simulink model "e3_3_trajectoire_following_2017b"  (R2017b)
settings: Solver=FixedStepAuto  StartTime=0.0  StopTime=100  FixedStep=1/120  RelTol=1e-3  EnableMultiTasking=on
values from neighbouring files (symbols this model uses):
  a = XMAX    (= 0.8)    [start_tello.m]
  b = YMAX    (= 1.2)    [start_tello.m]
  battery_threshold = 15    [start_tello.m]
  bb = (ZMIN*YMAX - ZMAX*YMIN)/(YMAX - YMIN)    (= -1.05)    [start_tello.m]
  k = (ZMAX - ZMIN)/(YMAX - YMIN)    (= 0.458333333333)    [start_tello.m]
  omega = 0.3    [start_tello.m]
  R = 1    [start_tello.m]
  sim_end_time = 15*act_end + 4    (= 475.238898038)    [start_tello.m]
  tb2 = tb    (= 2.7)    [start_tello.m]
  tb3 = tb*2    (= 5.4)    [start_tello.m]
  tb4 = tb*3    (= 8.1)    [start_tello.m]
  tb5 = tb*4    (= 10.8)    [start_tello.m]
  tb6 = tb*5    (= 13.5)    [start_tello.m]
  tb7 = tb*6    (= 16.2)    [start_tello.m]
  tb8 = tb*7    (= 18.9)    [start_tello.m]
  TELLO1_NUM = uint8(1)    [start_tello.m]
  TELLO2_NUM = uint8(2)    [start_tello.m]
  TELLO3_NUM = uint8(3)    [start_tello.m]
  TELLO4_NUM = uint8(4)    [start_tello.m]
  TELLO5_NUM = uint8(5)    [start_tello.m]
  TELLO6_NUM = uint8(6)    [start_tello.m]
  TELLO7_NUM = uint8(7)    [start_tello.m]
  TELLO8_NUM = uint8(8)    [start_tello.m]
  UAV_NUM = 0    [start_tello.m]
  w1 = 0.4    [start_tello.m]
  w2 = 0.2    [start_tello.m]
  z_d_for_land = -0.2    [start_tello.m]
libraries: simulink x51, etargetslib x24, dspnetwork x24, sharedtransform x8, aerolibanimutils x1
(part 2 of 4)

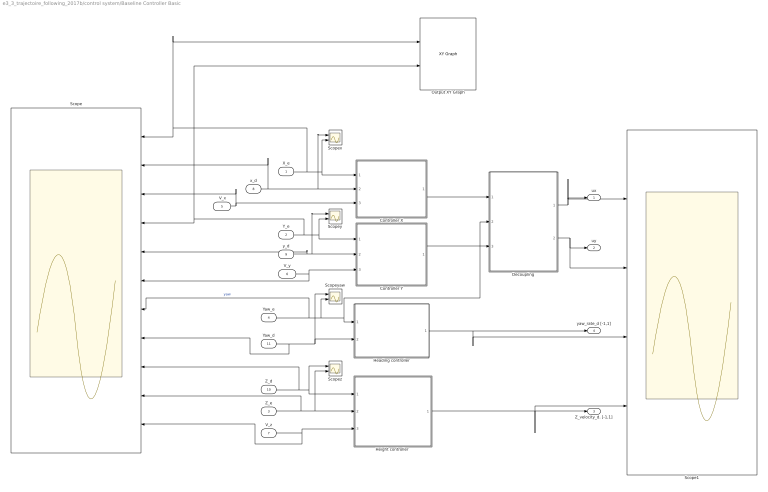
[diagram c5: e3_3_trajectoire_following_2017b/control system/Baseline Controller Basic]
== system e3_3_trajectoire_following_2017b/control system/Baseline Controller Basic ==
  X_e : Inport
  Y_e : Inport  Port=2
  " Z_e " : Inport  Port=3
  Yaw_e : Inport  Port=4
  " V_x" : Inport  Port=5
  V_y : Inport  Port=6
  V_z : Inport  Port=7
  x_d : Inport  Port=8
  y_d : Inport  Port=9
  Z_d : Inport  Port=10
  Yaw_d : Inport  Port=11
  Controller X : Subsystem
  Controller Y : Subsystem
  Decoupling : Subsystem
  Heading controller : Subsystem
  "Height controller " : Subsystem
  Output XY Graph : simulink/Sinks/XY Graph  xmin=-1  xmax=1  ymin=-1  ymax=1  st=-1
  Scope : Scope  NumInputPorts=11
  Scope1 : Scope  NumInputPorts=4
  Scopex : Scope  NumInputPorts=2
  Scopey : Scope  NumInputPorts=2
  Scopeyaw : Scope  NumInputPorts=2
  Scopez : Scope  NumInputPorts=2
  ux : Outport  VectorParamsAs1DForOutWhenUnconnected=off
  uy : Outport  Port=2  VectorParamsAs1DForOutWhenUnconnected=off
  Z_velocity_d. [-1,1] : Outport  Port=3  VectorParamsAs1DForOutWhenUnconnected=off
  yaw_rate_d [-1,1] : Outport  Port=4  VectorParamsAs1DForOutWhenUnconnected=off
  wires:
  x_d/1 -> Controller X/2(X_d (m)), Scopex/1, Scope/2
  Z_d/1 -> Scope/9, "Height controller "/1(Z_d. (m)), Scopez/1
  Y_e/1 -> Controller Y/1(Y_e (m)), Scopey/2, Output XY Graph/2, Scope/4
  Yaw_d/1 -> Scope/8, Heading controller/2(yaw_d. (rad)), Scopeyaw/1
  "Height controller "/1(Z_velocity_d (m/s)) -> Scope1/4, Z_velocity_d. [-1,1]/1
  X_e/1 -> Output XY Graph/1, Scope/1, Controller X/1(X_e (m)), Scopex/2
  " Z_e "/1 -> Scope/10, "Height controller "/2(Z_e (m)), Scopez/2
  Heading controller/1(yaw_rate_d. (rad/s)) -> yaw_rate_d [-1,1]/1, Scope1/3
  Yaw_e/1 -> Scope/7, Heading controller/1(yaw_e (rad)), Decoupling/2(yaw_e), Scopeyaw/2  "yaw"
  V_z/1 -> "Height controller "/3(V_z), Scope/11
  y_d/1 -> Scope/5, Controller Y/2(Y_d (m)), Scopey/1
  Decoupling/1(D_Ux) -> Scope1/1, ux/1
  Decoupling/2(D_Uy) -> Scope1/2, uy/1
  Controller Y/1(uy) -> Decoupling/3(Uy)
  Controller X/1(U_x) -> Decoupling/1(Ux)
  " V_x"/1 -> Controller X/3(V_x_e), Scope/3
  V_y/1 -> Controller Y/3(V_y_e), Scope/6

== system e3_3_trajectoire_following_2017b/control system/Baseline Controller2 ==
  X_e : Inport
  Y_e : Inport  Port=2
  " Z_e " : Inport  Port=3
  Yaw_e : Inport  Port=4
  " V_x" : Inport  Port=5
  V_y : Inport  Port=6
  "V_z " : Inport  Port=7
  x_d : Inport  Port=8
  y_d : Inport  Port=9
  Z_d : Inport  Port=10
  Yaw_d : Inport  Port=11
  Constant : Constant  Value=omega*R*2
  Demux : Demux  Outputs=2
  Heading controller : Subsystem
  "Height controller " : Subsystem
  MATLAB Function : MATLAB Function  TreatAsAtomicUnit=on
  Position controller : Subsystem
  ux : Outport  VectorParamsAs1DForOutWhenUnconnected=off
  uy : Outport  Port=2  VectorParamsAs1DForOutWhenUnconnected=off
  Z_velocity_d. [-1,1] : Outport  Port=3  VectorParamsAs1DForOutWhenUnconnected=off
  yaw_rate_d [-1,1] : Outport  Port=4  VectorParamsAs1DForOutWhenUnconnected=off
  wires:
  Position controller/1(uxy) -> MATLAB Function/1(u)
  "V_z "/1 -> "Height controller "/3(V_z)
  Yaw_e/1 -> Position controller/5(Yaw_e (rad)), Heading controller/1(yaw_e (rad))  "yaw"
  y_d/1 -> Position controller/4(Y_d (m))
  x_d/1 -> Position controller/3(X_d (m))
  Z_d/1 -> "Height controller "/1(Z_d. (m))
  Constant/1 -> MATLAB Function/2(a)
  Demux/2 -> uy/1
  Demux/1 -> ux/1
  MATLAB Function/1(y) -> Demux/1
  Yaw_d/1 -> Heading controller/2(yaw_d. (rad))
  Y_e/1 -> Position controller/2(Y_e (m))
  X_e/1 -> Position controller/1(X_e (m))
  Heading controller/1(yaw_rate_d. (rad/s)) -> yaw_rate_d [-1,1]/1
  "Height controller "/1(Z_velocity_d (m/s)) -> Z_velocity_d. [-1,1]/1
  " Z_e "/1 -> "Height controller "/2(Z_e (m))

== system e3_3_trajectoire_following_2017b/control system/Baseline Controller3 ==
  X_e : Inport
  Y_e : Inport  Port=2
  " Z_e " : Inport  Port=3
  Yaw_e : Inport  Port=4
  " V_x" : Inport  Port=5
  V_y : Inport  Port=6
  "V_z " : Inport  Port=7
  x_d : Inport  Port=8
  y_d : Inport  Port=9
  Z_d : Inport  Port=10
  Yaw_d : Inport  Port=11
  Constant : Constant  Value=omega*R*2
  Demux : Demux  Outputs=2
  Heading controller : Subsystem
  "Height controller " : Subsystem
  MATLAB Function : MATLAB Function  TreatAsAtomicUnit=on
  Position controller : Subsystem
  ux : Outport  VectorParamsAs1DForOutWhenUnconnected=off
  uy : Outport  Port=2  VectorParamsAs1DForOutWhenUnconnected=off
  Z_velocity_d. [-1,1] : Outport  Port=3  VectorParamsAs1DForOutWhenUnconnected=off
  yaw_rate_d [-1,1] : Outport  Port=4  VectorParamsAs1DForOutWhenUnconnected=off
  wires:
  " Z_e "/1 -> "Height controller "/2(Z_e (m))
  "Height controller "/1(Z_velocity_d (m/s)) -> Z_velocity_d. [-1,1]/1
  Heading controller/1(yaw_rate_d. (rad/s)) -> yaw_rate_d [-1,1]/1
  X_e/1 -> Position controller/1(X_e (m))
  Y_e/1 -> Position controller/2(Y_e (m))
  Yaw_d/1 -> Heading controller/2(yaw_d. (rad))
  MATLAB Function/1(y) -> Demux/1
  Demux/1 -> ux/1
  Demux/2 -> uy/1
  Constant/1 -> MATLAB Function/2(a)
  Z_d/1 -> "Height controller "/1(Z_d. (m))
  x_d/1 -> Position controller/3(X_d (m))
  y_d/1 -> Position controller/4(Y_d (m))
  Yaw_e/1 -> Heading controller/1(yaw_e (rad)), Position controller/5(Yaw_e (rad))  "yaw"
  "V_z "/1 -> "Height controller "/3(V_z)
  Position controller/1(uxy) -> MATLAB Function/1(u)

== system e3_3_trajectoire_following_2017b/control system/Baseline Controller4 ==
  X_e : Inport
  Y_e : Inport  Port=2
  " Z_e " : Inport  Port=3
  Yaw_e : Inport  Port=4
  " V_x" : Inport  Port=5
  V_y : Inport  Port=6
  "V_z " : Inport  Port=7
  x_d : Inport  Port=8
  y_d : Inport  Port=9
  Z_d : Inport  Port=10
  Yaw_d : Inport  Port=11
  Constant : Constant  Value=omega*R*2
  Demux : Demux  Outputs=2
  Heading controller : Subsystem
  "Height controller " : Subsystem
  MATLAB Function : MATLAB Function  TreatAsAtomicUnit=on
  Position controller : Subsystem
  ux : Outport  VectorParamsAs1DForOutWhenUnconnected=off
  uy : Outport  Port=2  VectorParamsAs1DForOutWhenUnconnected=off
  Z_velocity_d. [-1,1] : Outport  Port=3  VectorParamsAs1DForOutWhenUnconnected=off
  yaw_rate_d [-1,1] : Outport  Port=4  VectorParamsAs1DForOutWhenUnconnected=off
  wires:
  Position controller/1(uxy) -> MATLAB Function/1(u)
  "V_z "/1 -> "Height controller "/3(V_z)
  Yaw_e/1 -> Position controller/5(Yaw_e (rad)), Heading controller/1(yaw_e (rad))  "yaw"
  y_d/1 -> Position controller/4(Y_d (m))
  x_d/1 -> Position controller/3(X_d (m))
  Z_d/1 -> "Height controller "/1(Z_d. (m))
  Constant/1 -> MATLAB Function/2(a)
  Demux/2 -> uy/1
  Demux/1 -> ux/1
  MATLAB Function/1(y) -> Demux/1
  Yaw_d/1 -> Heading controller/2(yaw_d. (rad))
  Y_e/1 -> Position controller/2(Y_e (m))
  X_e/1 -> Position controller/1(X_e (m))
  Heading controller/1(yaw_rate_d. (rad/s)) -> yaw_rate_d [-1,1]/1
  "Height controller "/1(Z_velocity_d (m/s)) -> Z_velocity_d. [-1,1]/1
  " Z_e "/1 -> "Height controller "/2(Z_e (m))

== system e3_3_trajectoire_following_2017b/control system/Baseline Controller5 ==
  X_e : Inport
  Y_e : Inport  Port=2
  " Z_e " : Inport  Port=3
  Yaw_e : Inport  Port=4
  " V_x" : Inport  Port=5
  V_y : Inport  Port=6
  "V_z " : Inport  Port=7
  x_d : Inport  Port=8
  y_d : Inport  Port=9
  Z_d : Inport  Port=10
  Yaw_d : Inport  Port=11
  Constant : Constant  Value=omega*R*2
  Demux : Demux  Outputs=2
  Heading controller : Subsystem
  "Height controller " : Subsystem
  MATLAB Function : MATLAB Function  TreatAsAtomicUnit=on
  Position controller : Subsystem
  ux : Outport  VectorParamsAs1DForOutWhenUnconnected=off
  uy : Outport  Port=2  VectorParamsAs1DForOutWhenUnconnected=off
  Z_velocity_d. [-1,1] : Outport  Port=3  VectorParamsAs1DForOutWhenUnconnected=off
  yaw_rate_d [-1,1] : Outport  Port=4  VectorParamsAs1DForOutWhenUnconnected=off
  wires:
  " Z_e "/1 -> "Height controller "/2(Z_e (m))
  "Height controller "/1(Z_velocity_d (m/s)) -> Z_velocity_d. [-1,1]/1
  Heading controller/1(yaw_rate_d. (rad/s)) -> yaw_rate_d [-1,1]/1
  X_e/1 -> Position controller/1(X_e (m))
  Y_e/1 -> Position controller/2(Y_e (m))
  Yaw_d/1 -> Heading controller/2(yaw_d. (rad))
  MATLAB Function/1(y) -> Demux/1
  Demux/1 -> ux/1
  Demux/2 -> uy/1
  Constant/1 -> MATLAB Function/2(a)
  Z_d/1 -> "Height controller "/1(Z_d. (m))
  x_d/1 -> Position controller/3(X_d (m))
  y_d/1 -> Position controller/4(Y_d (m))
  Yaw_e/1 -> Heading controller/1(yaw_e (rad)), Position controller/5(Yaw_e (rad))  "yaw"
  "V_z "/1 -> "Height controller "/3(V_z)
  Position controller/1(uxy) -> MATLAB Function/1(u)

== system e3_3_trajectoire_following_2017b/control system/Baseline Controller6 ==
  X_e : Inport
  Y_e : Inport  Port=2
  " Z_e " : Inport  Port=3
  Yaw_e : Inport  Port=4
  " V_x" : Inport  Port=5
  V_y : Inport  Port=6
  "V_z " : Inport  Port=7
  x_d : Inport  Port=8
  y_d : Inport  Port=9
  Z_d : Inport  Port=10
  Yaw_d : Inport  Port=11
  Constant : Constant  Value=omega*R*2
  Demux : Demux  Outputs=2
  Heading controller : Subsystem
  "Height controller " : Subsystem
  MATLAB Function : MATLAB Function  TreatAsAtomicUnit=on
  Position controller : Subsystem
  ux : Outport  VectorParamsAs1DForOutWhenUnconnected=off
  uy : Outport  Port=2  VectorParamsAs1DForOutWhenUnconnected=off
  Z_velocity_d. [-1,1] : Outport  Port=3  VectorParamsAs1DForOutWhenUnconnected=off
  yaw_rate_d [-1,1] : Outport  Port=4  VectorParamsAs1DForOutWhenUnconnected=off
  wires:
  Position controller/1(uxy) -> MATLAB Function/1(u)
  "V_z "/1 -> "Height controller "/3(V_z)
  Yaw_e/1 -> Position controller/5(Yaw_e (rad)), Heading controller/1(yaw_e (rad))  "yaw"
  y_d/1 -> Position controller/4(Y_d (m))
  x_d/1 -> Position controller/3(X_d (m))
  Z_d/1 -> "Height controller "/1(Z_d. (m))
  Constant/1 -> MATLAB Function/2(a)
  Demux/2 -> uy/1
  Demux/1 -> ux/1
  MATLAB Function/1(y) -> Demux/1
  Yaw_d/1 -> Heading controller/2(yaw_d. (rad))
  Y_e/1 -> Position controller/2(Y_e (m))
  X_e/1 -> Position controller/1(X_e (m))
  Heading controller/1(yaw_rate_d. (rad/s)) -> yaw_rate_d [-1,1]/1
  "Height controller "/1(Z_velocity_d (m/s)) -> Z_velocity_d. [-1,1]/1
  " Z_e "/1 -> "Height controller "/2(Z_e (m))

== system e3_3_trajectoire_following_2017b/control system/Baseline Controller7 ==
  X_e : Inport
  Y_e : Inport  Port=2
  " Z_e " : Inport  Port=3
  Yaw_e : Inport  Port=4
  " V_x" : Inport  Port=5
  V_y : Inport  Port=6
  "V_z " : Inport  Port=7
  x_d : Inport  Port=8
  y_d : Inport  Port=9
  Z_d : Inport  Port=10
  Yaw_d : Inport  Port=11
  Constant : Constant  Value=omega*R*2
  Demux : Demux  Outputs=2
  Heading controller : Subsystem
  "Height controller " : Subsystem
  MATLAB Function : MATLAB Function  TreatAsAtomicUnit=on
  Position controller : Subsystem
  ux : Outport  VectorParamsAs1DForOutWhenUnconnected=off
  uy : Outport  Port=2  VectorParamsAs1DForOutWhenUnconnected=off
  Z_velocity_d. [-1,1] : Outport  Port=3  VectorParamsAs1DForOutWhenUnconnected=off
  yaw_rate_d [-1,1] : Outport  Port=4  VectorParamsAs1DForOutWhenUnconnected=off
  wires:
  " Z_e "/1 -> "Height controller "/2(Z_e (m))
  "Height controller "/1(Z_velocity_d (m/s)) -> Z_velocity_d. [-1,1]/1
  Heading controller/1(yaw_rate_d. (rad/s)) -> yaw_rate_d [-1,1]/1
  X_e/1 -> Position controller/1(X_e (m))
  Y_e/1 -> Position controller/2(Y_e (m))
  Yaw_d/1 -> Heading controller/2(yaw_d. (rad))
  MATLAB Function/1(y) -> Demux/1
  Demux/1 -> ux/1
  Demux/2 -> uy/1
  Constant/1 -> MATLAB Function/2(a)
  Z_d/1 -> "Height controller "/1(Z_d. (m))
  x_d/1 -> Position controller/3(X_d (m))
  y_d/1 -> Position controller/4(Y_d (m))
  Yaw_e/1 -> Heading controller/1(yaw_e (rad)), Position controller/5(Yaw_e (rad))  "yaw"
  "V_z "/1 -> "Height controller "/3(V_z)
  Position controller/1(uxy) -> MATLAB Function/1(u)

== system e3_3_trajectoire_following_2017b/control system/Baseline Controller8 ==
  X_e : Inport
  Y_e : Inport  Port=2
  " Z_e " : Inport  Port=3
  Yaw_e : Inport  Port=4
  " V_x" : Inport  Port=5
  V_y : Inport  Port=6
  "V_z " : Inport  Port=7
  x_d : Inport  Port=8
  y_d : Inport  Port=9
  Z_d : Inport  Port=10
  Yaw_d : Inport  Port=11
  Constant : Constant  Value=omega*R*2
  Demux : Demux  Outputs=2
  Heading controller : Subsystem
  "Height controller " : Subsystem
  MATLAB Function : MATLAB Function  TreatAsAtomicUnit=on
  Position controller : Subsystem
  ux : Outport  VectorParamsAs1DForOutWhenUnconnected=off
  uy : Outport  Port=2  VectorParamsAs1DForOutWhenUnconnected=off
  Z_velocity_d. [-1,1] : Outport  Port=3  VectorParamsAs1DForOutWhenUnconnected=off
  yaw_rate_d [-1,1] : Outport  Port=4  VectorParamsAs1DForOutWhenUnconnected=off
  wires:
  Position controller/1(uxy) -> MATLAB Function/1(u)
  "V_z "/1 -> "Height controller "/3(V_z)
  Yaw_e/1 -> Position controller/5(Yaw_e (rad)), Heading controller/1(yaw_e (rad))  "yaw"
  y_d/1 -> Position controller/4(Y_d (m))
  x_d/1 -> Position controller/3(X_d (m))
  Z_d/1 -> "Height controller "/1(Z_d. (m))
  Constant/1 -> MATLAB Function/2(a)
  Demux/2 -> uy/1
  Demux/1 -> ux/1
  MATLAB Function/1(y) -> Demux/1
  Yaw_d/1 -> Heading controller/2(yaw_d. (rad))
  Y_e/1 -> Position controller/2(Y_e (m))
  X_e/1 -> Position controller/1(X_e (m))
  Heading controller/1(yaw_rate_d. (rad/s)) -> yaw_rate_d [-1,1]/1
  "Height controller "/1(Z_velocity_d (m/s)) -> Z_velocity_d. [-1,1]/1
  " Z_e "/1 -> "Height controller "/2(Z_e (m))

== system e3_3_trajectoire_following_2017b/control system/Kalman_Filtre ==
  Pos_Real : Inport
  Velocity_Real : Inport  Port=2
  Bus Creator12 : BusCreator  Inputs=3
  Demux : Demux
  Demux1 : Demux  Outputs=3
  Kalman Filtre H : Subsystem
  Kalman Filtre Psi : Subsystem
  Kalman Filtre X : Subsystem
  Kalman Filtre Y : Subsystem
  Velocity_Feedback : Outport  VectorParamsAs1DForOutWhenUnconnected=off
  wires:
  Pos_Real/1 -> Demux/1
  Demux/3 -> Kalman Filtre H/1(The system output: Position)
  Kalman Filtre X/1(Out velocity feedback) -> Bus Creator12/1
  Demux/1 -> Kalman Filtre X/1(The system output: Position)
  Demux/4 -> Kalman Filtre Psi/1(The system output: Position)
  Kalman Filtre H/1(Out velocity feedback) -> Bus Creator12/3
  Kalman Filtre Y/1(Out velocity feedback) -> Bus Creator12/2
  Velocity_Real/1 -> Demux1/1
  Bus Creator12/1 -> Velocity_Feedback/1
  Demux1/1 -> Kalman Filtre X/2(real_vx)
  Demux/2 -> Kalman Filtre Y/1(The system output: Position)
  Demux1/3 -> Kalman Filtre H/2(real_vz)
  Demux1/2 -> Kalman Filtre Y/2(real_vy)

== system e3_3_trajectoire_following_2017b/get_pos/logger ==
  tello1_states : Inport
  Bus Selector1 : BusSelector  OutputSignals=x1,y1,z1,yaw1
  Bus Selector2 : BusSelector  OutputSignals=vx1,vy1,vz1
  To Workspace : ToWorkspace  VariableName=posx  SampleTime=-1
  To Workspace1 : ToWorkspace  VariableName=posy  SampleTime=-1
  To Workspace2 : ToWorkspace  VariableName=posz  SampleTime=-1
  To Workspace3 : ToWorkspace  VariableName=yaw  SampleTime=-1
  To Workspace4 : ToWorkspace  VariableName=velx  SampleTime=-1
  To Workspace5 : ToWorkspace  VariableName=vely  SampleTime=-1
  To Workspace6 : ToWorkspace  VariableName=velz  SampleTime=-1
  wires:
  Bus Selector2/2 -> To Workspace5/1  "<vy1>"
  Bus Selector1/3 -> To Workspace2/1  "<z1>"
  Bus Selector2/1 -> To Workspace4/1  "<vx1>"
  Bus Selector1/4 -> To Workspace3/1  "<yaw1>"
  Bus Selector1/1 -> To Workspace/1  "<x1>"
  tello1_states/1 -> Bus Selector1/1, Bus Selector2/1
  Bus Selector1/2 -> To Workspace1/1  "<y1>"
  Bus Selector2/3 -> To Workspace6/1  "<vz1>"

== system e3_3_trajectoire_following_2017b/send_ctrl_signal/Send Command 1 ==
  pos : Inport
  u : Inport  Port=2
  Bus Selector : BusSelector  OutputSignals=tello1_states.z1
  Bus Selector1 : BusSelector  OutputSignals=tello1.u_vx,tello1.u_vy,tello1.u_vz,tello1.u_rate_roll,tello1.u_rate_pitch,tello1.u_rate_yaw
  Byte Pack : etargetslib/Byte Pack  datatypes={'uint8','double','double','double','double','double','double'}  byteAlign=1
  Clock : Clock
  Compare To Constant : simulink/Logic and Bit Operations/Compare To Constant  relop=>=  const=0.1  OutDataTypeStr=boolean
  Compare To Constant1 : simulink/Logic and Bit Operations/Compare To Constant  relop=<  const=0  OutDataTypeStr=boolean
  Constant : Constant  Value=sim_end_time
  Constant1 : Constant  Value=0
  Constant2 : Constant  Value=TELLO1_NUM
  K : Gain  Gain=-1
  K1 : Gain
  K2 : Gain  Gain=-1
  Logical Operator : Logic  AllPortsSameDT=off  OutDataTypeStr=boolean
  Sum : Sum  Inputs=|-+
  Switch{1..3,12} (4 alike) : Switch  Criteria=u2 > Threshold  Threshold=0.001
  UDP Send7 : dspnetwork/UDP Send  remoteURL=UDP_SEND_IP  remotePort=TELLO1_SEND_PORT  localURL='0.0.0.0'  localPortSource=Automatically determine  localPort=-1  sampletime=-1  blockPlatform=[]  separateLengthPort=0
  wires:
  Constant1/1 -> Switch3/3, Switch2/3, Switch1/3, Switch12/3
  K/1 -> Byte Pack/3
  K1/1 -> Byte Pack/7
  Switch12/1 -> Byte Pack/2
  Switch1/1 -> K/1
  Bus Selector1/2 -> Switch1/1  "<u_vy>"
  Switch2/1 -> K2/1
  Bus Selector1/3 -> Switch2/1  "<u_vz>"
  Switch3/1 -> K1/1
  Logical Operator/1 -> Switch1/2, Switch12/2, Switch2/2, Switch3/2
  K2/1 -> Byte Pack/4
  Clock/1 -> Sum/1
  Constant/1 -> Sum/2
  Sum/1 -> Compare To Constant/1
  Compare To Constant/1 -> Logical Operator/2
  pos/1 -> Bus Selector/1
  Bus Selector/1 -> Compare To Constant1/1  "<z1>"
  u/1 -> Bus Selector1/1
  Bus Selector1/1 -> Switch12/1  "<u_vx>"
  Bus Selector1/6 -> Switch3/1  "<u_rate_yaw>"
  Bus Selector1/4 -> Byte Pack/5  "<u_rate_roll>"
  Bus Selector1/5 -> Byte Pack/6  "<u_rate_pitch>"
  Compare To Constant1/1 -> Logical Operator/1
  Byte Pack/1 -> UDP Send7/1
  Constant2/1 -> Byte Pack/1

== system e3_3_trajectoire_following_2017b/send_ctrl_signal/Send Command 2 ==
  pos : Inport
  u : Inport  Port=2
  Bus Selector : BusSelector  OutputSignals=tello2_states.z2
  Bus Selector1 : BusSelector  OutputSignals=tello2.u_vx,tello2.u_vy,tello2.u_vz,tello2.u_rate_roll,tello2.u_rate_pitch,tello2.u_rate_yaw
  Byte Pack : etargetslib/Byte Pack  datatypes={'uint8','double','double','double','double','double','double'}  byteAlign=1
  Clock : Clock
  Compare To Constant : simulink/Logic and Bit Operations/Compare To Constant  relop=>=  const=0.1  OutDataTypeStr=boolean
  Compare To Constant1 : simulink/Logic and Bit Operations/Compare To Constant  relop=<  const=0  OutDataTypeStr=boolean
  Constant : Constant  Value=sim_end_time
  Constant1 : Constant  Value=0
  Constant2 : Constant  Value=TELLO2_NUM
  K : Gain  Gain=-1
  K1 : Gain
  K2 : Gain  Gain=-1
  Logical Operator : Logic  AllPortsSameDT=off  OutDataTypeStr=boolean
  Sum : Sum  Inputs=|-+
  Switch{1..3,12} (4 alike) : Switch  Criteria=u2 > Threshold  Threshold=0.001
  UDP Send7 : dspnetwork/UDP Send  remoteURL=UDP_SEND_IP  remotePort=TELLO2_SEND_PORT  localURL='0.0.0.0'  localPortSource=Automatically determine  localPort=-1  sampletime=-1  blockPlatform=[]  separateLengthPort=0
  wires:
  Constant1/1 -> Switch3/3, Switch2/3, Switch1/3, Switch12/3
  K/1 -> Byte Pack/3
  K1/1 -> Byte Pack/7
  Switch12/1 -> Byte Pack/2
  Switch1/1 -> K/1
  Bus Selector1/2 -> Switch1/1  "<u_vy>"
  Switch2/1 -> K2/1
  Bus Selector1/3 -> Switch2/1  "<u_vz>"
  Switch3/1 -> K1/1
  Logical Operator/1 -> Switch1/2, Switch12/2, Switch2/2, Switch3/2
  K2/1 -> Byte Pack/4
  Clock/1 -> Sum/1
  Constant/1 -> Sum/2
  Sum/1 -> Compare To Constant/1
  Compare To Constant/1 -> Logical Operator/2
  pos/1 -> Bus Selector/1
  Bus Selector/1 -> Compare To Constant1/1  "<z2>"
  u/1 -> Bus Selector1/1
  Bus Selector1/1 -> Switch12/1  "<u_vx>"
  Bus Selector1/6 -> Switch3/1  "<u_rate_yaw>"
  Bus Selector1/4 -> Byte Pack/5  "<u_rate_roll>"
  Bus Selector1/5 -> Byte Pack/6  "<u_rate_pitch>"
  Compare To Constant1/1 -> Logical Operator/1
  Byte Pack/1 -> UDP Send7/1
  Constant2/1 -> Byte Pack/1

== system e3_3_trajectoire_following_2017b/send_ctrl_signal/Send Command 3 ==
  pos : Inport
  u : Inport  Port=2
  Bus Selector : BusSelector  OutputSignals=tello3_states.z3
  Bus Selector1 : BusSelector  OutputSignals=tello3.u_vx,tello3.u_vy,tello3.u_vz,tello3.u_rate_roll,tello3.u_rate_pitch,tello3.u_rate_yaw
  Byte Pack : etargetslib/Byte Pack  datatypes={'uint8','double','double','double','double','double','double'}  byteAlign=1
  Clock : Clock
  Compare To Constant : simulink/Logic and Bit Operations/Compare To Constant  relop=>=  const=0.1  OutDataTypeStr=boolean
  Compare To Constant1 : simulink/Logic and Bit Operations/Compare To Constant  relop=<  const=0  OutDataTypeStr=boolean
  Constant : Constant  Value=sim_end_time
  Constant1 : Constant  Value=0
  Constant2 : Constant  Value=TELLO3_NUM
  K : Gain  Gain=-1
  K1 : Gain
  K2 : Gain  Gain=-1
  Logical Operator : Logic  AllPortsSameDT=off  OutDataTypeStr=boolean
  Sum : Sum  Inputs=|-+
  Switch{1..3,12} (4 alike) : Switch  Criteria=u2 > Threshold  Threshold=0.001
  UDP Send7 : dspnetwork/UDP Send  remoteURL=UDP_SEND_IP  remotePort=TELLO3_SEND_PORT  localURL='0.0.0.0'  localPortSource=Automatically determine  localPort=-1  sampletime=-1  blockPlatform=[]  separateLengthPort=0
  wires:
  Constant1/1 -> Switch3/3, Switch2/3, Switch1/3, Switch12/3
  K/1 -> Byte Pack/3
  K1/1 -> Byte Pack/7
  Switch12/1 -> Byte Pack/2
  Switch1/1 -> K/1
  Bus Selector1/2 -> Switch1/1  "<u_vy>"
  Switch2/1 -> K2/1
  Bus Selector1/3 -> Switch2/1  "<u_vz>"
  Switch3/1 -> K1/1
  Logical Operator/1 -> Switch1/2, Switch12/2, Switch2/2, Switch3/2
  K2/1 -> Byte Pack/4
  Clock/1 -> Sum/1
  Constant/1 -> Sum/2
  Sum/1 -> Compare To Constant/1
  Compare To Constant/1 -> Logical Operator/2
  pos/1 -> Bus Selector/1
  Bus Selector/1 -> Compare To Constant1/1  "<z3>"
  u/1 -> Bus Selector1/1
  Bus Selector1/1 -> Switch12/1  "<u_vx>"
  Bus Selector1/6 -> Switch3/1  "<u_rate_yaw>"
  Bus Selector1/4 -> Byte Pack/5  "<u_rate_roll>"
  Bus Selector1/5 -> Byte Pack/6  "<u_rate_pitch>"
  Compare To Constant1/1 -> Logical Operator/1
  Byte Pack/1 -> UDP Send7/1
  Constant2/1 -> Byte Pack/1

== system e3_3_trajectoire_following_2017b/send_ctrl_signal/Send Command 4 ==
  pos : Inport
  u : Inport  Port=2
  Bus Selector : BusSelector  OutputSignals=tello4_states.z4
  Bus Selector1 : BusSelector  OutputSignals=tello4.u_vx,tello4.u_vy,tello4.u_vz,tello4.u_rate_roll,tello4.u_rate_pitch,tello4.u_rate_yaw
  Byte Pack : etargetslib/Byte Pack  datatypes={'uint8','double','double','double','double','double','double'}  byteAlign=1
  Clock : Clock
  Compare To Constant : simulink/Logic and Bit Operations/Compare To Constant  relop=>=  const=0.1  OutDataTypeStr=boolean
  Compare To Constant1 : simulink/Logic and Bit Operations/Compare To Constant  relop=<  const=0  OutDataTypeStr=boolean
  Constant : Constant  Value=sim_end_time
  Constant1 : Constant  Value=0
  Constant2 : Constant  Value=TELLO4_NUM
  K : Gain  Gain=-1
  K1 : Gain
  K2 : Gain  Gain=-1
  Logical Operator : Logic  AllPortsSameDT=off  OutDataTypeStr=boolean
  Sum : Sum  Inputs=|-+
  Switch{1..3,12} (4 alike) : Switch  Criteria=u2 > Threshold  Threshold=0.001
  UDP Send7 : dspnetwork/UDP Send  remoteURL=UDP_SEND_IP  remotePort=TELLO4_SEND_PORT  localURL='0.0.0.0'  localPortSource=Automatically determine  localPort=-1  sampletime=-1  blockPlatform=[]  separateLengthPort=0
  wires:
  Constant1/1 -> Switch3/3, Switch2/3, Switch1/3, Switch12/3
  K/1 -> Byte Pack/3
  K1/1 -> Byte Pack/7
  Switch12/1 -> Byte Pack/2
  Switch1/1 -> K/1
  Bus Selector1/2 -> Switch1/1  "<u_vy>"
  Switch2/1 -> K2/1
  Bus Selector1/3 -> Switch2/1  "<u_vz>"
  Switch3/1 -> K1/1
  Logical Operator/1 -> Switch1/2, Switch12/2, Switch2/2, Switch3/2
  K2/1 -> Byte Pack/4
  Clock/1 -> Sum/1
  Constant/1 -> Sum/2
  Sum/1 -> Compare To Constant/1
  Compare To Constant/1 -> Logical Operator/2
  pos/1 -> Bus Selector/1
  Bus Selector/1 -> Compare To Constant1/1  "<z4>"
  u/1 -> Bus Selector1/1
  Bus Selector1/1 -> Switch12/1  "<u_vx>"
  Bus Selector1/6 -> Switch3/1  "<u_rate_yaw>"
  Bus Selector1/4 -> Byte Pack/5  "<u_rate_roll>"
  Bus Selector1/5 -> Byte Pack/6  "<u_rate_pitch>"
  Compare To Constant1/1 -> Logical Operator/1
  Byte Pack/1 -> UDP Send7/1
  Constant2/1 -> Byte Pack/1

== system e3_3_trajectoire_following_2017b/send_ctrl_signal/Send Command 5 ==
  pos : Inport
  u : Inport  Port=2
  Bus Selector : BusSelector  OutputSignals=tello5_states.z5
  Bus Selector1 : BusSelector  OutputSignals=tello5.u_vx,tello5.u_vy,tello5.u_vz,tello5.u_rate_roll,tello5.u_rate_pitch,tello5.u_rate_yaw
  Byte Pack : etargetslib/Byte Pack  datatypes={'uint8','double','double','double','double','double','double'}  byteAlign=1
  Clock : Clock
  Compare To Constant : simulink/Logic and Bit Operations/Compare To Constant  relop=>=  const=0.1  OutDataTypeStr=boolean
  Compare To Constant1 : simulink/Logic and Bit Operations/Compare To Constant  relop=<  const=0  OutDataTypeStr=boolean
  Constant : Constant  Value=sim_end_time
  Constant1 : Constant  Value=0
  Constant2 : Constant  Value=TELLO5_NUM
  K : Gain  Gain=-1
  K1 : Gain
  K2 : Gain  Gain=-1
  Logical Operator : Logic  AllPortsSameDT=off  OutDataTypeStr=boolean
  Sum : Sum  Inputs=|-+
  Switch{1..3,12} (4 alike) : Switch  Criteria=u2 > Threshold  Threshold=0.001
  UDP Send7 : dspnetwork/UDP Send  remoteURL=UDP_SEND_IP  remotePort=TELLO5_SEND_PORT  localURL='0.0.0.0'  localPortSource=Automatically determine  localPort=-1  sampletime=-1  blockPlatform=[]  separateLengthPort=0
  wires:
  Constant1/1 -> Switch3/3, Switch2/3, Switch1/3, Switch12/3
  K/1 -> Byte Pack/3
  K1/1 -> Byte Pack/7
  Switch12/1 -> Byte Pack/2
  Switch1/1 -> K/1
  Bus Selector1/2 -> Switch1/1  "<u_vy>"
  Switch2/1 -> K2/1
  Bus Selector1/3 -> Switch2/1  "<u_vz>"
  Switch3/1 -> K1/1
  Logical Operator/1 -> Switch1/2, Switch12/2, Switch2/2, Switch3/2
  K2/1 -> Byte Pack/4
  Clock/1 -> Sum/1
  Constant/1 -> Sum/2
  Sum/1 -> Compare To Constant/1
  Compare To Constant/1 -> Logical Operator/2
  pos/1 -> Bus Selector/1
  Bus Selector/1 -> Compare To Constant1/1  "<z5>"
  u/1 -> Bus Selector1/1
  Bus Selector1/1 -> Switch12/1  "<u_vx>"
  Bus Selector1/6 -> Switch3/1  "<u_rate_yaw>"
  Bus Selector1/4 -> Byte Pack/5  "<u_rate_roll>"
  Bus Selector1/5 -> Byte Pack/6  "<u_rate_pitch>"
  Compare To Constant1/1 -> Logical Operator/1
  Byte Pack/1 -> UDP Send7/1
  Constant2/1 -> Byte Pack/1

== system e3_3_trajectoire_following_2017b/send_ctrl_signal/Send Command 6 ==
  pos : Inport
  u : Inport  Port=2
  Bus Selector : BusSelector  OutputSignals=tello6_states.z6
  Bus Selector1 : BusSelector  OutputSignals=tello6.u_vx,tello6.u_vy,tello6.u_vz,tello6.u_rate_roll,tello6.u_rate_pitch,tello6.u_rate_yaw
  Byte Pack : etargetslib/Byte Pack  datatypes={'uint8','double','double','double','double','double','double'}  byteAlign=1
  Clock : Clock
  Compare To Constant : simulink/Logic and Bit Operations/Compare To Constant  relop=>=  const=0.1  OutDataTypeStr=boolean
  Compare To Constant1 : simulink/Logic and Bit Operations/Compare To Constant  relop=<  const=0  OutDataTypeStr=boolean
  Constant : Constant  Value=sim_end_time
  Constant1 : Constant  Value=0
  Constant2 : Constant  Value=TELLO6_NUM
  K : Gain  Gain=-1
  K1 : Gain
  K2 : Gain  Gain=-1
  Logical Operator : Logic  AllPortsSameDT=off  OutDataTypeStr=boolean
  Sum : Sum  Inputs=|-+
  Switch{1..3,12} (4 alike) : Switch  Criteria=u2 > Threshold  Threshold=0.001
  UDP Send7 : dspnetwork/UDP Send  remoteURL=UDP_SEND_IP  remotePort=TELLO6_SEND_PORT  localURL='0.0.0.0'  localPortSource=Automatically determine  localPort=-1  sampletime=-1  blockPlatform=[]  separateLengthPort=0
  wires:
  Constant1/1 -> Switch3/3, Switch2/3, Switch1/3, Switch12/3
  K/1 -> Byte Pack/3
  K1/1 -> Byte Pack/7
  Switch12/1 -> Byte Pack/2
  Switch1/1 -> K/1
  Bus Selector1/2 -> Switch1/1  "<u_vy>"
  Switch2/1 -> K2/1
  Bus Selector1/3 -> Switch2/1  "<u_vz>"
  Switch3/1 -> K1/1
  Logical Operator/1 -> Switch1/2, Switch12/2, Switch2/2, Switch3/2
  K2/1 -> Byte Pack/4
  Clock/1 -> Sum/1
  Constant/1 -> Sum/2
  Sum/1 -> Compare To Constant/1
  Compare To Constant/1 -> Logical Operator/2
  pos/1 -> Bus Selector/1
  Bus Selector/1 -> Compare To Constant1/1  "<z6>"
  u/1 -> Bus Selector1/1
  Bus Selector1/1 -> Switch12/1  "<u_vx>"
  Bus Selector1/6 -> Switch3/1  "<u_rate_yaw>"
  Bus Selector1/4 -> Byte Pack/5  "<u_rate_roll>"
  Bus Selector1/5 -> Byte Pack/6  "<u_rate_pitch>"
  Compare To Constant1/1 -> Logical Operator/1
  Byte Pack/1 -> UDP Send7/1
  Constant2/1 -> Byte Pack/1

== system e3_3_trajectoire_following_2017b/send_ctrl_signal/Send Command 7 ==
  pos : Inport
  u : Inport  Port=2
  Bus Selector : BusSelector  OutputSignals=tello7_states.z7
  Bus Selector1 : BusSelector  OutputSignals=tello7.u_vx,tello7.u_vy,tello7.u_vz,tello7.u_rate_roll,tello7.u_rate_pitch,tello7.u_rate_yaw
  Byte Pack : etargetslib/Byte Pack  datatypes={'uint8','double','double','double','double','double','double'}  byteAlign=1
  Clock : Clock
  Compare To Constant : simulink/Logic and Bit Operations/Compare To Constant  relop=>=  const=0.1  OutDataTypeStr=boolean
  Compare To Constant1 : simulink/Logic and Bit Operations/Compare To Constant  relop=<  const=0  OutDataTypeStr=boolean
  Constant : Constant  Value=sim_end_time
  Constant1 : Constant  Value=0
  Constant2 : Constant  Value=TELLO7_NUM
  K : Gain  Gain=-1
  K1 : Gain
  K2 : Gain  Gain=-1
  Logical Operator : Logic  AllPortsSameDT=off  OutDataTypeStr=boolean
  Sum : Sum  Inputs=|-+
  Switch{1..3,12} (4 alike) : Switch  Criteria=u2 > Threshold  Threshold=0.001
  UDP Send7 : dspnetwork/UDP Send  remoteURL=UDP_SEND_IP  remotePort=TELLO7_SEND_PORT  localURL='0.0.0.0'  localPortSource=Automatically determine  localPort=-1  sampletime=-1  blockPlatform=[]  separateLengthPort=0
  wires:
  Constant1/1 -> Switch3/3, Switch2/3, Switch1/3, Switch12/3
  K/1 -> Byte Pack/3
  K1/1 -> Byte Pack/7
  Switch12/1 -> Byte Pack/2
  Switch1/1 -> K/1
  Bus Selector1/2 -> Switch1/1  "<u_vy>"
  Switch2/1 -> K2/1
  Bus Selector1/3 -> Switch2/1  "<u_vz>"
  Switch3/1 -> K1/1
  Logical Operator/1 -> Switch1/2, Switch12/2, Switch2/2, Switch3/2
  K2/1 -> Byte Pack/4
  Clock/1 -> Sum/1
  Constant/1 -> Sum/2
  Sum/1 -> Compare To Constant/1
  Compare To Constant/1 -> Logical Operator/2
  pos/1 -> Bus Selector/1
  Bus Selector/1 -> Compare To Constant1/1  "<z7>"
  u/1 -> Bus Selector1/1
  Bus Selector1/1 -> Switch12/1  "<u_vx>"
  Bus Selector1/6 -> Switch3/1  "<u_rate_yaw>"
  Bus Selector1/4 -> Byte Pack/5  "<u_rate_roll>"
  Bus Selector1/5 -> Byte Pack/6  "<u_rate_pitch>"
  Compare To Constant1/1 -> Logical Operator/1
  Byte Pack/1 -> UDP Send7/1
  Constant2/1 -> Byte Pack/1

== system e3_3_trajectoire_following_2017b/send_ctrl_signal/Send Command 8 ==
  pos : Inport
  u : Inport  Port=2
  Bus Selector : BusSelector  OutputSignals=tello8_states.z8
  Bus Selector1 : BusSelector  OutputSignals=tello8.u_vx,tello8.u_vy,tello8.u_vz,tello8.u_rate_roll,tello8.u_rate_pitch,tello8.u_rate_yaw
  Byte Pack : etargetslib/Byte Pack  datatypes={'uint8','double','double','double','double','double','double'}  byteAlign=1
  Clock : Clock
  Compare To Constant : simulink/Logic and Bit Operations/Compare To Constant  relop=>=  const=0.1  OutDataTypeStr=boolean
  Compare To Constant1 : simulink/Logic and Bit Operations/Compare To Constant  relop=<  const=0  OutDataTypeStr=boolean
  Constant : Constant  Value=sim_end_time
  Constant1 : Constant  Value=0
  Constant2 : Constant  Value=TELLO8_NUM
  K : Gain  Gain=-1
  K1 : Gain
  K2 : Gain  Gain=-1
  Logical Operator : Logic  AllPortsSameDT=off  OutDataTypeStr=boolean
  Sum : Sum  Inputs=|-+
  Switch{1..3,12} (4 alike) : Switch  Criteria=u2 > Threshold  Threshold=0.001
  UDP Send7 : dspnetwork/UDP Send  remoteURL=UDP_SEND_IP  remotePort=TELLO8_SEND_PORT  localURL='0.0.0.0'  localPortSource=Automatically determine  localPort=-1  sampletime=-1  blockPlatform=[]  separateLengthPort=0
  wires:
  Constant1/1 -> Switch3/3, Switch2/3, Switch1/3, Switch12/3
  K/1 -> Byte Pack/3
  K1/1 -> Byte Pack/7
  Switch12/1 -> Byte Pack/2
  Switch1/1 -> K/1
  Bus Selector1/2 -> Switch1/1  "<u_vy>"
  Switch2/1 -> K2/1
  Bus Selector1/3 -> Switch2/1  "<u_vz>"
  Switch3/1 -> K1/1
  Logical Operator/1 -> Switch1/2, Switch12/2, Switch2/2, Switch3/2
  K2/1 -> Byte Pack/4
  Clock/1 -> Sum/1
  Constant/1 -> Sum/2
  Sum/1 -> Compare To Constant/1
  Compare To Constant/1 -> Logical Operator/2
  pos/1 -> Bus Selector/1
  Bus Selector/1 -> Compare To Constant1/1  "<z8>"
  u/1 -> Bus Selector1/1
  Bus Selector1/1 -> Switch12/1  "<u_vx>"
  Bus Selector1/6 -> Switch3/1  "<u_rate_yaw>"
  Bus Selector1/4 -> Byte Pack/5  "<u_rate_roll>"
  Bus Selector1/5 -> Byte Pack/6  "<u_rate_pitch>"
  Compare To Constant1/1 -> Logical Operator/1
  Byte Pack/1 -> UDP Send7/1
  Constant2/1 -> Byte Pack/1

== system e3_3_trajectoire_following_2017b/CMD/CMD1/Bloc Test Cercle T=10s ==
  note: 机头指向圆心飞圆，X通道sin(wt)，Y通道cos(wt)，Psi通道sin(wt+pi)。 三者的周期 需要一致才能达到此效果。
  Constant2 : Constant
  Sine Wave : Sin  Frequency=0.65  Phase=pi  SampleTime=0
  Sine Wave X : Sin  Frequency=0.65  SampleTime=0
  Sine Wave Y : Sin  Frequency=0.65  Phase=pi/2  SampleTime=0
  Slider Gain1 : simulink/Math Operations/Slider Gain  gain=1  low=-10  high=10
  Slider Gain2 : simulink/Math Operations/Slider Gain  gain=1  low=-10  high=10
  Slider Gain3 : simulink/Math Operations/Slider Gain  gain=2  low=-2  high=2
  Slider Gain4 : simulink/Math Operations/Slider Gain  gain=1  low=-2  high=2
  ux : Outport  VectorParamsAs1DForOutWhenUnconnected=off
  uy : Outport  Port=2  VectorParamsAs1DForOutWhenUnconnected=off
  uz : Outport  Port=3  VectorParamsAs1DForOutWhenUnconnected=off
  upsi : Outport  Port=4  VectorParamsAs1DForOutWhenUnconnected=off
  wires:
  Slider Gain2/1 -> uy/1
  Slider Gain3/1 -> uz/1
  Slider Gain4/1 -> upsi/1
  Slider Gain1/1 -> ux/1
  Constant2/1 -> Slider Gain3/1
  Sine Wave/1 -> Slider Gain4/1
  Sine Wave X/1 -> Slider Gain1/1
  Sine Wave Y/1 -> Slider Gain2/1

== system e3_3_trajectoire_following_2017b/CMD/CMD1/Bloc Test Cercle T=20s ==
  note: 机头指向圆心飞圆，X通道sin(wt)，Y通道cos(wt)，Psi通道sin(wt+pi)。 三者的周期 需要一致才能达到此效果。
  Constant2 : Constant
  Sine Wave : Sin  Frequency=0.35  Phase=pi  SampleTime=0
  Sine Wave X : Sin  Frequency=0.35  SampleTime=0
  Sine Wave Y : Sin  Frequency=0.35  Phase=pi/2  SampleTime=0
  Slider Gain1 : simulink/Math Operations/Slider Gain  gain=1  low=-10  high=10
  Slider Gain2 : simulink/Math Operations/Slider Gain  gain=1  low=-10  high=10
  Slider Gain3 : simulink/Math Operations/Slider Gain  gain=2  low=-2  high=2
  Slider Gain4 : simulink/Math Operations/Slider Gain  gain=1  low=-2  high=2
  ux : Outport  VectorParamsAs1DForOutWhenUnconnected=off
  uy : Outport  Port=2  VectorParamsAs1DForOutWhenUnconnected=off
  uz : Outport  Port=3  VectorParamsAs1DForOutWhenUnconnected=off
  upsi : Outport  Port=4  VectorParamsAs1DForOutWhenUnconnected=off
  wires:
  Slider Gain2/1 -> uy/1
  Slider Gain3/1 -> uz/1
  Slider Gain4/1 -> upsi/1
  Slider Gain1/1 -> ux/1
  Constant2/1 -> Slider Gain3/1
  Sine Wave/1 -> Slider Gain4/1
  Sine Wave X/1 -> Slider Gain1/1
  Sine Wave Y/1 -> Slider Gain2/1

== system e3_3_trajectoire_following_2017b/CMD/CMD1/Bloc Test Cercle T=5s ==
  note: 机头指向圆心飞圆，X通道sin(wt)，Y通道cos(wt)，Psi通道sin(wt+pi)。 三者的周期 需要一致才能达到此效果。
  Constant2 : Constant
  Sine Wave : Sin  Phase=pi  SampleTime=0
  Sine Wave X : Sin  SampleTime=0
  Sine Wave Y : Sin  Phase=pi/2  SampleTime=0
  Slider Gain1 : simulink/Math Operations/Slider Gain  gain=1  low=-10  high=10
  Slider Gain2 : simulink/Math Operations/Slider Gain  gain=1  low=-10  high=10
  Slider Gain3 : simulink/Math Operations/Slider Gain  gain=2  low=-2  high=2
  Slider Gain4 : simulink/Math Operations/Slider Gain  gain=1  low=-2  high=2
  ux : Outport  VectorParamsAs1DForOutWhenUnconnected=off
  uy : Outport  Port=2  VectorParamsAs1DForOutWhenUnconnected=off
  uz : Outport  Port=3  VectorParamsAs1DForOutWhenUnconnected=off
  upsi : Outport  Port=4  VectorParamsAs1DForOutWhenUnconnected=off
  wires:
  Slider Gain2/1 -> uy/1
  Slider Gain3/1 -> uz/1
  Slider Gain4/1 -> upsi/1
  Slider Gain1/1 -> ux/1
  Constant2/1 -> Slider Gain3/1
  Sine Wave/1 -> Slider Gain4/1
  Sine Wave X/1 -> Slider Gain1/1
  Sine Wave Y/1 -> Slider Gain2/1

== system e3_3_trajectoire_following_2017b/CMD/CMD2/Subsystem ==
  clock : Inport
  Constant1 : Constant  Value=k
  Constant10 : Constant  Value=tb4
  Constant2 : Constant  Value=sim_end_time
  Constant3 : Constant  Value=bb
  Constant4 : Constant  Value=w1
  Constant5 : Constant  Value=a
  Constant6 : Constant  Value=w2
  Constant7 : Constant  Value=b
  Constant8 : Constant  Value=tb2
  Constant9 : Constant  Value=tb3
  MATLAB Function : MATLAB Function  TreatAsAtomicUnit=on
  "x " : Outport  VectorParamsAs1DForOutWhenUnconnected=off
  y : Outport  Port=2  VectorParamsAs1DForOutWhenUnconnected=off
  z : Outport  Port=3  VectorParamsAs1DForOutWhenUnconnected=off
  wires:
  MATLAB Function/1(x2_) -> "x "/1
  MATLAB Function/2(y2_) -> y/1
  MATLAB Function/3(z2_) -> z/1
  clock/1 -> MATLAB Function/1(timestamp)
  Constant2/1 -> MATLAB Function/2(sim_end_time)
  Constant5/1 -> MATLAB Function/3(a)
  Constant7/1 -> MATLAB Function/4(b)
  Constant1/1 -> MATLAB Function/5(k)
  Constant3/1 -> MATLAB Function/6(bb)
  Constant4/1 -> MATLAB Function/7(w1)
  Constant6/1 -> MATLAB Function/8(w2)
  Constant8/1 -> MATLAB Function/9(tb2)
  Constant9/1 -> MATLAB Function/10(tb3)
  Constant10/1 -> MATLAB Function/11(tb4)

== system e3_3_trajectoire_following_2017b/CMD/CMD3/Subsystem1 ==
  clock : Inport
  Constant1 : Constant  Value=k
  Constant10 : Constant  Value=tb4
  Constant2 : Constant  Value=sim_end_time
  Constant3 : Constant  Value=bb
  Constant4 : Constant  Value=w1
  Constant5 : Constant  Value=a
  Constant6 : Constant  Value=w2
  Constant7 : Constant  Value=b
  Constant8 : Constant  Value=tb2
  Constant9 : Constant  Value=tb3
  MATLAB Function : MATLAB Function  TreatAsAtomicUnit=on
  "x " : Outport  VectorParamsAs1DForOutWhenUnconnected=off
  y : Outport  Port=2  VectorParamsAs1DForOutWhenUnconnected=off
  z : Outport  Port=3  VectorParamsAs1DForOutWhenUnconnected=off
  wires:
  Constant10/1 -> MATLAB Function/11(tb4)
  Constant9/1 -> MATLAB Function/10(tb3)
  Constant8/1 -> MATLAB Function/9(tb2)
  Constant6/1 -> MATLAB Function/8(w2)
  Constant4/1 -> MATLAB Function/7(w1)
  Constant3/1 -> MATLAB Function/6(bb)
  Constant1/1 -> MATLAB Function/5(k)
  Constant7/1 -> MATLAB Function/4(b)
  Constant5/1 -> MATLAB Function/3(a)
  Constant2/1 -> MATLAB Function/2(sim_end_time)
  clock/1 -> MATLAB Function/1(timestamp)
  MATLAB Function/3(z3_) -> z/1
  MATLAB Function/2(y3_) -> y/1
  MATLAB Function/1(x3_) -> "x "/1

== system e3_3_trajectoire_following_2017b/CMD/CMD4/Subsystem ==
  clock : Inport
  Constant1 : Constant  Value=k
  Constant10 : Constant  Value=tb4
  Constant2 : Constant  Value=sim_end_time
  Constant3 : Constant  Value=bb
  Constant4 : Constant  Value=w1
  Constant5 : Constant  Value=a
  Constant6 : Constant  Value=w2
  Constant7 : Constant  Value=b
  Constant8 : Constant  Value=tb2
  Constant9 : Constant  Value=tb3
  MATLAB Function : MATLAB Function  TreatAsAtomicUnit=on
  "x " : Outport  VectorParamsAs1DForOutWhenUnconnected=off
  y : Outport  Port=2  VectorParamsAs1DForOutWhenUnconnected=off
  z : Outport  Port=3  VectorParamsAs1DForOutWhenUnconnected=off
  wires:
  MATLAB Function/1(x4_) -> "x "/1
  MATLAB Function/2(y4_) -> y/1
  MATLAB Function/3(z4_) -> z/1
  clock/1 -> MATLAB Function/1(timestamp)
  Constant2/1 -> MATLAB Function/2(sim_end_time)
  Constant5/1 -> MATLAB Function/3(a)
  Constant7/1 -> MATLAB Function/4(b)
  Constant1/1 -> MATLAB Function/5(k)
  Constant3/1 -> MATLAB Function/6(bb)
  Constant4/1 -> MATLAB Function/7(w1)
  Constant6/1 -> MATLAB Function/8(w2)
  Constant8/1 -> MATLAB Function/9(tb2)
  Constant9/1 -> MATLAB Function/10(tb3)
  Constant10/1 -> MATLAB Function/11(tb4)

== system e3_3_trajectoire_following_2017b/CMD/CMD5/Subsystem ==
  clock : Inport
  Constant1 : Constant  Value=k
  Constant10 : Constant  Value=tb4
  Constant11 : Constant  Value=tb8
  Constant12 : Constant  Value=tb6
  Constant13 : Constant  Value=tb7
  Constant14 : Constant  Value=tb5
  Constant2 : Constant  Value=sim_end_time
  Constant3 : Constant  Value=bb
  Constant4 : Constant  Value=w1
  Constant5 : Constant  Value=a
  Constant6 : Constant  Value=w2
  Constant7 : Constant  Value=b
  Constant8 : Constant  Value=tb2
  Constant9 : Constant  Value=tb3
  MATLAB Function : MATLAB Function  TreatAsAtomicUnit=on
  "x " : Outport  VectorParamsAs1DForOutWhenUnconnected=off
  y : Outport  Port=2  VectorParamsAs1DForOutWhenUnconnected=off
  z : Outport  Port=3  VectorParamsAs1DForOutWhenUnconnected=off
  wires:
  MATLAB Function/1(x5_) -> "x "/1
  MATLAB Function/2(y5_) -> y/1
  MATLAB Function/3(z5_) -> z/1
  clock/1 -> MATLAB Function/1(timestamp)
  Constant2/1 -> MATLAB Function/2(sim_end_time)
  Constant5/1 -> MATLAB Function/3(a)
  Constant7/1 -> MATLAB Function/4(b)
  Constant1/1 -> MATLAB Function/5(k)
  Constant3/1 -> MATLAB Function/6(bb)
  Constant4/1 -> MATLAB Function/7(w1)
  Constant6/1 -> MATLAB Function/8(w2)
  Constant8/1 -> MATLAB Function/9(tb2)
  Constant9/1 -> MATLAB Function/10(tb3)
  Constant10/1 -> MATLAB Function/11(tb4)
  Constant11/1 -> MATLAB Function/15(tb8)
  Constant13/1 -> MATLAB Function/14(tb7)
  Constant12/1 -> MATLAB Function/13(tb6)
  Constant14/1 -> MATLAB Function/12(tb5)

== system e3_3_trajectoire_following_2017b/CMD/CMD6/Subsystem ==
  clock : Inport
  Constant1 : Constant  Value=k
  Constant10 : Constant  Value=tb4
  Constant11 : Constant  Value=tb8
  Constant12 : Constant  Value=tb6
  Constant13 : Constant  Value=tb7
  Constant14 : Constant  Value=tb5
  Constant2 : Constant  Value=sim_end_time
  Constant3 : Constant  Value=bb
  Constant4 : Constant  Value=w1
  Constant5 : Constant  Value=a
  Constant6 : Constant  Value=w2
  Constant7 : Constant  Value=b
  Constant8 : Constant  Value=tb2
  Constant9 : Constant  Value=tb3
  MATLAB Function : MATLAB Function  TreatAsAtomicUnit=on
  "x " : Outport  VectorParamsAs1DForOutWhenUnconnected=off
  y : Outport  Port=2  VectorParamsAs1DForOutWhenUnconnected=off
  z : Outport  Port=3  VectorParamsAs1DForOutWhenUnconnected=off
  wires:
  MATLAB Function/1(x6_) -> "x "/1
  MATLAB Function/2(y6_) -> y/1
  MATLAB Function/3(z6_) -> z/1
  clock/1 -> MATLAB Function/1(timestamp)
  Constant2/1 -> MATLAB Function/2(sim_end_time)
  Constant5/1 -> MATLAB Function/3(a)
  Constant7/1 -> MATLAB Function/4(b)
  Constant1/1 -> MATLAB Function/5(k)
  Constant3/1 -> MATLAB Function/6(bb)
  Constant4/1 -> MATLAB Function/7(w1)
  Constant6/1 -> MATLAB Function/8(w2)
  Constant8/1 -> MATLAB Function/9(tb2)
  Constant9/1 -> MATLAB Function/10(tb3)
  Constant10/1 -> MATLAB Function/11(tb4)
  Constant11/1 -> MATLAB Function/15(tb8)
  Constant13/1 -> MATLAB Function/14(tb7)
  Constant12/1 -> MATLAB Function/13(tb6)
  Constant14/1 -> MATLAB Function/12(tb5)

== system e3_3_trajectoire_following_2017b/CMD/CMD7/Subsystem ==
  clock : Inport
  Constant1 : Constant  Value=k
  Constant10 : Constant  Value=tb4
  Constant11 : Constant  Value=tb8
  Constant12 : Constant  Value=tb6
  Constant13 : Constant  Value=tb7
  Constant14 : Constant  Value=tb5
  Constant2 : Constant  Value=sim_end_time
  Constant3 : Constant  Value=bb
  Constant4 : Constant  Value=w1
  Constant5 : Constant  Value=a
  Constant6 : Constant  Value=w2
  Constant7 : Constant  Value=b
  Constant8 : Constant  Value=tb2
  Constant9 : Constant  Value=tb3
  MATLAB Function : MATLAB Function  TreatAsAtomicUnit=on
  "x " : Outport  VectorParamsAs1DForOutWhenUnconnected=off
  y : Outport  Port=2  VectorParamsAs1DForOutWhenUnconnected=off
  z : Outport  Port=3  VectorParamsAs1DForOutWhenUnconnected=off
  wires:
  MATLAB Function/1(x7_) -> "x "/1
  MATLAB Function/2(y7_) -> y/1
  MATLAB Function/3(z7_) -> z/1
  clock/1 -> MATLAB Function/1(timestamp)
  Constant2/1 -> MATLAB Function/2(sim_end_time)
  Constant5/1 -> MATLAB Function/3(a)
  Constant7/1 -> MATLAB Function/4(b)
  Constant1/1 -> MATLAB Function/5(k)
  Constant3/1 -> MATLAB Function/6(bb)
  Constant4/1 -> MATLAB Function/7(w1)
  Constant6/1 -> MATLAB Function/8(w2)
  Constant8/1 -> MATLAB Function/9(tb2)
  Constant9/1 -> MATLAB Function/10(tb3)
  Constant10/1 -> MATLAB Function/11(tb4)
  Constant11/1 -> MATLAB Function/15(tb8)
  Constant13/1 -> MATLAB Function/14(tb7)
  Constant12/1 -> MATLAB Function/13(tb6)
  Constant14/1 -> MATLAB Function/12(tb5)

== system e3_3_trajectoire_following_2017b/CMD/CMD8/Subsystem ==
  clock : Inport
  Constant1 : Constant  Value=k
  Constant10 : Constant  Value=tb4
  Constant11 : Constant  Value=tb8
  Constant12 : Constant  Value=tb6
  Constant13 : Constant  Value=tb7
  Constant14 : Constant  Value=tb5
  Constant2 : Constant  Value=sim_end_time
  Constant3 : Constant  Value=bb
  Constant4 : Constant  Value=w1
  Constant5 : Constant  Value=a
  Constant6 : Constant  Value=w2
  Constant7 : Constant  Value=b
  Constant8 : Constant  Value=tb2
  Constant9 : Constant  Value=tb3
  MATLAB Function : MATLAB Function  TreatAsAtomicUnit=on
  "x " : Outport  VectorParamsAs1DForOutWhenUnconnected=off
  y : Outport  Port=2  VectorParamsAs1DForOutWhenUnconnected=off
  z : Outport  Port=3  VectorParamsAs1DForOutWhenUnconnected=off
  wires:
  MATLAB Function/1(x8_) -> "x "/1
  MATLAB Function/2(y8_) -> y/1
  MATLAB Function/3(z8_) -> z/1
  clock/1 -> MATLAB Function/1(timestamp)
  Constant2/1 -> MATLAB Function/2(sim_end_time)
  Constant5/1 -> MATLAB Function/3(a)
  Constant7/1 -> MATLAB Function/4(b)
  Constant1/1 -> MATLAB Function/5(k)
  Constant3/1 -> MATLAB Function/6(bb)
  Constant4/1 -> MATLAB Function/7(w1)
  Constant6/1 -> MATLAB Function/8(w2)
  Constant8/1 -> MATLAB Function/9(tb2)
  Constant9/1 -> MATLAB Function/10(tb3)
  Constant10/1 -> MATLAB Function/11(tb4)
  Constant11/1 -> MATLAB Function/15(tb8)
  Constant13/1 -> MATLAB Function/14(tb7)
  Constant12/1 -> MATLAB Function/13(tb6)
  Constant14/1 -> MATLAB Function/12(tb5)

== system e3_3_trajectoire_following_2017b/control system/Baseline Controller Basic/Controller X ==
  X_e (m) : Inport
  X_d (m) : Inport  Port=2
  V_x_e : Inport  Port=3
  Integrator Limited1 : Integrator  LimitOutput=on  UpperSaturationLimit=0.5  LowerSaturationLimit=-0.5
  Kd1 : Gain  Gain=0.58
  Kp2 : Gain  Gain=0.4
  Kp3 : Gain  Gain=0.03
  Sum5 : Sum  Inputs=++-
  Sum6 : Sum  Inputs=|-+
  Transfer Fcn1 : TransferFcn  Denominator=[1/(2*pi*5) 1]
  U_x : Outport  VectorParamsAs1DForOutWhenUnconnected=off
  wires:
  X_d (m)/1 -> Sum6/2
  X_e (m)/1 -> Sum6/1
  Integrator Limited1/1 -> Sum5/1
  Kp3/1 -> Integrator Limited1/1
  Kd1/1 -> Sum5/3
  Transfer Fcn1/1 -> Kd1/1
  Sum5/1 -> U_x/1
  V_x_e/1 -> Transfer Fcn1/1
  Kp2/1 -> Sum5/2
  Sum6/1 -> Kp3/1, Kp2/1

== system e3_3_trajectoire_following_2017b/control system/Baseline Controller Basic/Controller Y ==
  Y_e (m) : Inport
  Y_d (m) : Inport  Port=2
  V_y_e : Inport  Port=3
  Integrator Limited1 : Integrator  LimitOutput=on  UpperSaturationLimit=0.5  LowerSaturationLimit=-0.5
  Kd1 : Gain  Gain=0.5
  Kp2 : Gain  Gain=0.45
  Kp3 : Gain  Gain=0.03
  Sum5 : Sum  Inputs=++-
  Sum6 : Sum  Inputs=|-+
  Transfer Fcn1 : TransferFcn  Denominator=[1/(2*pi*5) 1]
  uy : Outport  VectorParamsAs1DForOutWhenUnconnected=off
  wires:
  Y_d (m)/1 -> Sum6/2
  V_y_e/1 -> Transfer Fcn1/1
  Kp2/1 -> Sum5/2
  Sum5/1 -> uy/1
  Kd1/1 -> Sum5/3
  Y_e (m)/1 -> Sum6/1
  Transfer Fcn1/1 -> Kd1/1
  Sum6/1 -> Kp3/1, Kp2/1
  Kp3/1 -> Integrator Limited1/1
  Integrator Limited1/1 -> Sum5/1

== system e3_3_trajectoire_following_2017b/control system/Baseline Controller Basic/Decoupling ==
  note: car coordination
  Ux : Inport
  yaw_e : Inport  Port=2
  Uy : Inport  Port=3
  Constant : Constant  Value=omega*R*2
  "Coordinate trnasformation from inertial frame to body frame " : MATLAB Function  TreatAsAtomicUnit=on
  Demux : Demux  Outputs=2
  Gain1 : Gain  Gain=-1
  MATLAB Function : MATLAB Function  TreatAsAtomicUnit=on
  Mux : Mux  Inputs=2
  D_Ux : Outport  VectorParamsAs1DForOutWhenUnconnected=off
  D_Uy : Outport  Port=2  VectorParamsAs1DForOutWhenUnconnected=off
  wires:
  MATLAB Function/1(y) -> Demux/1
  Gain1/1 -> "Coordinate trnasformation from inertial frame to body frame "/2(psi)
  yaw_e/1 -> Gain1/1
  Demux/1 -> D_Ux/1
  Mux/1 -> "Coordinate trnasformation from inertial frame to body frame "/1(Vec_i)
  "Coordinate trnasformation from inertial frame to body frame "/1(Vec_xy) -> MATLAB Function/1(u)
  Demux/2 -> D_Uy/1
  Constant/1 -> MATLAB Function/2(a)
  Uy/1 -> Mux/2
  Ux/1 -> Mux/1
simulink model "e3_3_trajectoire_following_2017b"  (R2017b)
settings: Solver=FixedStepAuto  StartTime=0.0  StopTime=100  FixedStep=1/120  RelTol=1e-3  EnableMultiTasking=on
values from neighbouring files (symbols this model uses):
  a = XMAX    (= 0.8)    [start_tello.m]
  b = YMAX    (= 1.2)    [start_tello.m]
  battery_threshold = 15    [start_tello.m]
  bb = (ZMIN*YMAX - ZMAX*YMIN)/(YMAX - YMIN)    (= -1.05)    [start_tello.m]
  k = (ZMAX - ZMIN)/(YMAX - YMIN)    (= 0.458333333333)    [start_tello.m]
  omega = 0.3    [start_tello.m]
  R = 1    [start_tello.m]
  sim_end_time = 15*act_end + 4    (= 475.238898038)    [start_tello.m]
  tb2 = tb    (= 2.7)    [start_tello.m]
  tb3 = tb*2    (= 5.4)    [start_tello.m]
  tb4 = tb*3    (= 8.1)    [start_tello.m]
  tb5 = tb*4    (= 10.8)    [start_tello.m]
  tb6 = tb*5    (= 13.5)    [start_tello.m]
  tb7 = tb*6    (= 16.2)    [start_tello.m]
  tb8 = tb*7    (= 18.9)    [start_tello.m]
  TELLO1_NUM = uint8(1)    [start_tello.m]
  TELLO2_NUM = uint8(2)    [start_tello.m]
  TELLO3_NUM = uint8(3)    [start_tello.m]
  TELLO4_NUM = uint8(4)    [start_tello.m]
  TELLO5_NUM = uint8(5)    [start_tello.m]
  TELLO6_NUM = uint8(6)    [start_tello.m]
  TELLO7_NUM = uint8(7)    [start_tello.m]
  TELLO8_NUM = uint8(8)    [start_tello.m]
  UAV_NUM = 0    [start_tello.m]
  w1 = 0.4    [start_tello.m]
  w2 = 0.2    [start_tello.m]
  z_d_for_land = -0.2    [start_tello.m]
libraries: simulink x51, etargetslib x24, dspnetwork x24, sharedtransform x8, aerolibanimutils x1
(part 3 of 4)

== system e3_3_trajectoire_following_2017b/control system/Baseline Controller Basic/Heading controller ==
  yaw_e (rad) : Inport
  yaw_d. (rad) : Inport  Port=2
  Sum1 : Sum  Inputs=|-+
  Sum2 : Sum  Inputs=|++
  proportional control gain - yaw : Gain  Gain=1.9
  yaw_rate_d. (rad/s) : Outport  VectorParamsAs1DForOutWhenUnconnected=off
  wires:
  Sum1/1 -> proportional control gain - yaw/1
  yaw_e (rad)/1 -> Sum1/1
  yaw_d. (rad)/1 -> Sum1/2
  proportional control gain - yaw/1 -> Sum2/1
  Sum2/1 -> yaw_rate_d. (rad/s)/1

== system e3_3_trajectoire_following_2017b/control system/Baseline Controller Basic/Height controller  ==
  Z_d. (m) : Inport
  Z_e (m) : Inport  Port=2
  V_z : Inport  Port=3
  Integrator Limited : Integrator  LimitOutput=on  UpperSaturationLimit=0.5  LowerSaturationLimit=-0.5
  Kd : Gain
  Kp : Gain  Gain=2.5
  Kp2 : Gain  Gain=0.01
  Sum3 : Sum  Inputs=|-+
  Sum4 : Sum  Inputs=++-
  Transfer Fcn1 : TransferFcn  Denominator=[1/(2*pi*10) 1]
  Z_velocity_d (m/s) : Outport  VectorParamsAs1DForOutWhenUnconnected=off
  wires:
  Z_e (m)/1 -> Sum3/1
  Z_d. (m)/1 -> Sum3/2
  Kp/1 -> Sum4/2
  Sum4/1 -> Z_velocity_d (m/s)/1
  V_z/1 -> Transfer Fcn1/1
  Kd/1 -> Sum4/3
  Integrator Limited/1 -> Sum4/1
  Kp2/1 -> Integrator Limited/1
  Sum3/1 -> Kp2/1, Kp/1
  Transfer Fcn1/1 -> Kd/1

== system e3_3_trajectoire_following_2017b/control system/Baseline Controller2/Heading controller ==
  yaw_e (rad) : Inport
  yaw_d. (rad) : Inport  Port=2
  Integrator Limited : Integrator  Commented=on  LimitOutput=on  UpperSaturationLimit=0.3  LowerSaturationLimit=-0.3
  Ki : Gain  Commented=on  Gain=0.01
  Sum1 : Sum  Inputs=|-+
  Sum2 : Sum  Inputs=|++
  proportional control gain - yaw : Gain  Gain=1.0
  yaw_rate_d. (rad/s) : Outport  VectorParamsAs1DForOutWhenUnconnected=off
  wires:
  Sum2/1 -> yaw_rate_d. (rad/s)/1
  Ki/1 -> Integrator Limited/1
  Integrator Limited/1 -> Sum2/2
  proportional control gain - yaw/1 -> Sum2/1
  yaw_d. (rad)/1 -> Sum1/2
  yaw_e (rad)/1 -> Sum1/1
  Sum1/1 -> proportional control gain - yaw/1, Ki/1

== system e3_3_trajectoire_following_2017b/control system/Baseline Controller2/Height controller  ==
  Z_d. (m) : Inport
  Z_e (m) : Inport  Port=2
  V_z : Inport  Port=3
  Integrator Limited : Integrator  LimitOutput=on  UpperSaturationLimit=0.5  LowerSaturationLimit=-0.5
  Kd : Gain  Gain=0.01
  Kp : Gain  Gain=1.0
  Kp1 : Gain  Gain=0.01
  Sum1 : Sum  Inputs=|-+
  Sum2 : Sum  Inputs=+++
  Sum3 : Sum  Inputs=|-+
  Transfer Fcn1 : TransferFcn  Denominator=[1/(2*pi*10) 1]
  Z_velocity_d (m/s) : Outport  VectorParamsAs1DForOutWhenUnconnected=off
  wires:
  Z_d. (m)/1 -> Sum3/2
  Transfer Fcn1/1 -> Sum1/1
  Integrator Limited/1 -> Sum2/1
  Kp1/1 -> Integrator Limited/1
  Kd/1 -> Sum2/3
  Kp/1 -> Sum2/2
  Sum2/1 -> Z_velocity_d (m/s)/1
  Sum1/1 -> Kd/1
  V_z/1 -> Transfer Fcn1/1
  Z_e (m)/1 -> Sum3/1
  Sum3/1 -> Kp/1, Kp1/1

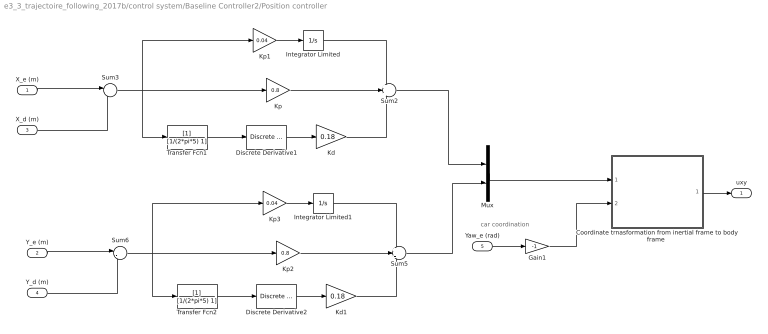
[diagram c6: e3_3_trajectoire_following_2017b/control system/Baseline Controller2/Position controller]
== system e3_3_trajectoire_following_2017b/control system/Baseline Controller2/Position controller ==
  note: car coordination
  X_e (m) : Inport
  Y_e (m) : Inport  Port=2
  X_d (m) : Inport  Port=3
  Y_d (m) : Inport  Port=4
  Yaw_e (rad) : Inport  Port=5
  "Coordinate trnasformation from inertial frame to body frame " : MATLAB Function  TreatAsAtomicUnit=on
  Discrete Derivative1 : simulink/Discrete/Discrete Derivative  gainval=1.0  ICPrevScaledInput=0.0  OutMin=[]  OutMax=[]  OutDataType=fixdt(1, 16)  OutScaling=2^-10  DoSatur=off
  Discrete Derivative2 : simulink/Discrete/Discrete Derivative  gainval=1.0  ICPrevScaledInput=0.0  OutMin=[]  OutMax=[]  OutDataType=fixdt(1, 16)  OutScaling=2^-10  DoSatur=off
  Gain1 : Gain  Gain=-1
  Integrator Limited : Integrator  LimitOutput=on  UpperSaturationLimit=0.5  LowerSaturationLimit=-0.5
  Integrator Limited1 : Integrator  LimitOutput=on  UpperSaturationLimit=0.5  LowerSaturationLimit=-0.5
  Kd : Gain  Gain=0.18
  Kd1 : Gain  Gain=0.18
  Kp : Gain  Gain=0.8
  Kp1 : Gain  Gain=0.04
  Kp2 : Gain  Gain=0.8
  Kp3 : Gain  Gain=0.04
  Mux : Mux  Inputs=2
  Sum2 : Sum  Inputs=+++
  Sum3 : Sum  Inputs=|-+
  Sum5 : Sum  Inputs=+++
  Sum6 : Sum  Inputs=|-+
  Transfer Fcn1 : TransferFcn  Denominator=[1/(2*pi*5) 1]
  Transfer Fcn2 : TransferFcn  Denominator=[1/(2*pi*5) 1]
  uxy : Outport  VectorParamsAs1DForOutWhenUnconnected=off
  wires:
  Sum6/1 -> Transfer Fcn2/1, Kp3/1, Kp2/1
  Discrete Derivative2/1 -> Kd1/1
  Kd1/1 -> Sum5/3
  Transfer Fcn2/1 -> Discrete Derivative2/1
  Y_d (m)/1 -> Sum6/2
  Transfer Fcn1/1 -> Discrete Derivative1/1
  Kd/1 -> Sum2/3
  Discrete Derivative1/1 -> Kd/1
  Sum3/1 -> Kp1/1, Transfer Fcn1/1, Kp/1
  X_d (m)/1 -> Sum3/2
  "Coordinate trnasformation from inertial frame to body frame "/1(Vec_xy) -> uxy/1
  Gain1/1 -> "Coordinate trnasformation from inertial frame to body frame "/2(psi)
  Mux/1 -> "Coordinate trnasformation from inertial frame to body frame "/1(Vec_i)
  Kp3/1 -> Integrator Limited1/1
  Sum5/1 -> Mux/2
  Integrator Limited1/1 -> Sum5/1
  Y_e (m)/1 -> Sum6/1
  Kp2/1 -> Sum5/2
  Kp/1 -> Sum2/2
  Kp1/1 -> Integrator Limited/1
  Sum2/1 -> Mux/1
  Integrator Limited/1 -> Sum2/1
  X_e (m)/1 -> Sum3/1
  Yaw_e (rad)/1 -> Gain1/1

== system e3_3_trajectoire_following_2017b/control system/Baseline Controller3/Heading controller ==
  yaw_e (rad) : Inport
  yaw_d. (rad) : Inport  Port=2
  Integrator Limited : Integrator  Commented=on  LimitOutput=on  UpperSaturationLimit=0.3  LowerSaturationLimit=-0.3
  Ki : Gain  Commented=on  Gain=0.01
  Sum1 : Sum  Inputs=|-+
  Sum2 : Sum  Inputs=|++
  proportional control gain - yaw : Gain  Gain=1.0
  yaw_rate_d. (rad/s) : Outport  VectorParamsAs1DForOutWhenUnconnected=off
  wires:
  Sum1/1 -> Ki/1, proportional control gain - yaw/1
  yaw_e (rad)/1 -> Sum1/1
  yaw_d. (rad)/1 -> Sum1/2
  proportional control gain - yaw/1 -> Sum2/1
  Integrator Limited/1 -> Sum2/2
  Ki/1 -> Integrator Limited/1
  Sum2/1 -> yaw_rate_d. (rad/s)/1

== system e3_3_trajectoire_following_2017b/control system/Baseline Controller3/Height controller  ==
  Z_d. (m) : Inport
  Z_e (m) : Inport  Port=2
  V_z : Inport  Port=3
  Integrator Limited : Integrator  LimitOutput=on  UpperSaturationLimit=0.5  LowerSaturationLimit=-0.5
  Kd : Gain  Gain=0.01
  Kp : Gain  Gain=1.0
  Kp1 : Gain  Gain=0.01
  Sum1 : Sum  Inputs=|-+
  Sum2 : Sum  Inputs=+++
  Sum3 : Sum  Inputs=|-+
  Transfer Fcn1 : TransferFcn  Denominator=[1/(2*pi*10) 1]
  Z_velocity_d (m/s) : Outport  VectorParamsAs1DForOutWhenUnconnected=off
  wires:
  Sum3/1 -> Kp1/1, Kp/1
  Z_e (m)/1 -> Sum3/1
  V_z/1 -> Transfer Fcn1/1
  Sum1/1 -> Kd/1
  Sum2/1 -> Z_velocity_d (m/s)/1
  Kp/1 -> Sum2/2
  Kd/1 -> Sum2/3
  Kp1/1 -> Integrator Limited/1
  Integrator Limited/1 -> Sum2/1
  Transfer Fcn1/1 -> Sum1/1
  Z_d. (m)/1 -> Sum3/2

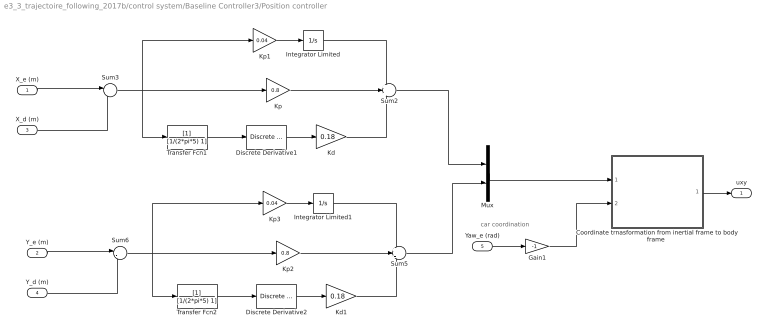
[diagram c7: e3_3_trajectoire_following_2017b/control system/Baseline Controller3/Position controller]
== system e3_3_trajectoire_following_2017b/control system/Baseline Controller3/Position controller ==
  note: car coordination
  X_e (m) : Inport
  Y_e (m) : Inport  Port=2
  X_d (m) : Inport  Port=3
  Y_d (m) : Inport  Port=4
  Yaw_e (rad) : Inport  Port=5
  "Coordinate trnasformation from inertial frame to body frame " : MATLAB Function  TreatAsAtomicUnit=on
  Discrete Derivative1 : simulink/Discrete/Discrete Derivative  gainval=1.0  ICPrevScaledInput=0.0  OutMin=[]  OutMax=[]  OutDataType=fixdt(1, 16)  OutScaling=2^-10  DoSatur=off
  Discrete Derivative2 : simulink/Discrete/Discrete Derivative  gainval=1.0  ICPrevScaledInput=0.0  OutMin=[]  OutMax=[]  OutDataType=fixdt(1, 16)  OutScaling=2^-10  DoSatur=off
  Gain1 : Gain  Gain=-1
  Integrator Limited : Integrator  LimitOutput=on  UpperSaturationLimit=0.5  LowerSaturationLimit=-0.5
  Integrator Limited1 : Integrator  LimitOutput=on  UpperSaturationLimit=0.5  LowerSaturationLimit=-0.5
  Kd : Gain  Gain=0.18
  Kd1 : Gain  Gain=0.18
  Kp : Gain  Gain=0.8
  Kp1 : Gain  Gain=0.04
  Kp2 : Gain  Gain=0.8
  Kp3 : Gain  Gain=0.04
  Mux : Mux  Inputs=2
  Sum2 : Sum  Inputs=+++
  Sum3 : Sum  Inputs=|-+
  Sum5 : Sum  Inputs=+++
  Sum6 : Sum  Inputs=|-+
  Transfer Fcn1 : TransferFcn  Denominator=[1/(2*pi*5) 1]
  Transfer Fcn2 : TransferFcn  Denominator=[1/(2*pi*5) 1]
  uxy : Outport  VectorParamsAs1DForOutWhenUnconnected=off
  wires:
  Yaw_e (rad)/1 -> Gain1/1
  X_e (m)/1 -> Sum3/1
  Integrator Limited/1 -> Sum2/1
  Sum2/1 -> Mux/1
  Kp1/1 -> Integrator Limited/1
  Kp/1 -> Sum2/2
  Kp2/1 -> Sum5/2
  Y_e (m)/1 -> Sum6/1
  Integrator Limited1/1 -> Sum5/1
  Sum5/1 -> Mux/2
  Kp3/1 -> Integrator Limited1/1
  Mux/1 -> "Coordinate trnasformation from inertial frame to body frame "/1(Vec_i)
  Gain1/1 -> "Coordinate trnasformation from inertial frame to body frame "/2(psi)
  "Coordinate trnasformation from inertial frame to body frame "/1(Vec_xy) -> uxy/1
  X_d (m)/1 -> Sum3/2
  Sum3/1 -> Kp/1, Transfer Fcn1/1, Kp1/1
  Discrete Derivative1/1 -> Kd/1
  Kd/1 -> Sum2/3
  Transfer Fcn1/1 -> Discrete Derivative1/1
  Y_d (m)/1 -> Sum6/2
  Transfer Fcn2/1 -> Discrete Derivative2/1
  Kd1/1 -> Sum5/3
  Discrete Derivative2/1 -> Kd1/1
  Sum6/1 -> Kp2/1, Kp3/1, Transfer Fcn2/1

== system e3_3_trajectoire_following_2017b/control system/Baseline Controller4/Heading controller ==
  yaw_e (rad) : Inport
  yaw_d. (rad) : Inport  Port=2
  Integrator Limited : Integrator  Commented=on  LimitOutput=on  UpperSaturationLimit=0.3  LowerSaturationLimit=-0.3
  Ki : Gain  Commented=on  Gain=0.01
  Sum1 : Sum  Inputs=|-+
  Sum2 : Sum  Inputs=|++
  proportional control gain - yaw : Gain  Gain=1.0
  yaw_rate_d. (rad/s) : Outport  VectorParamsAs1DForOutWhenUnconnected=off
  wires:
  Sum2/1 -> yaw_rate_d. (rad/s)/1
  Ki/1 -> Integrator Limited/1
  Integrator Limited/1 -> Sum2/2
  proportional control gain - yaw/1 -> Sum2/1
  yaw_d. (rad)/1 -> Sum1/2
  yaw_e (rad)/1 -> Sum1/1
  Sum1/1 -> proportional control gain - yaw/1, Ki/1

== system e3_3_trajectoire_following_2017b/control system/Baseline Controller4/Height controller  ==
  Z_d. (m) : Inport
  Z_e (m) : Inport  Port=2
  V_z : Inport  Port=3
  Integrator Limited : Integrator  LimitOutput=on  UpperSaturationLimit=0.5  LowerSaturationLimit=-0.5
  Kd : Gain  Gain=0.01
  Kp : Gain  Gain=1.0
  Kp1 : Gain  Gain=0.01
  Sum1 : Sum  Inputs=|-+
  Sum2 : Sum  Inputs=+++
  Sum3 : Sum  Inputs=|-+
  Transfer Fcn1 : TransferFcn  Denominator=[1/(2*pi*10) 1]
  Z_velocity_d (m/s) : Outport  VectorParamsAs1DForOutWhenUnconnected=off
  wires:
  Z_d. (m)/1 -> Sum3/2
  Transfer Fcn1/1 -> Sum1/1
  Integrator Limited/1 -> Sum2/1
  Kp1/1 -> Integrator Limited/1
  Kd/1 -> Sum2/3
  Kp/1 -> Sum2/2
  Sum2/1 -> Z_velocity_d (m/s)/1
  Sum1/1 -> Kd/1
  V_z/1 -> Transfer Fcn1/1
  Z_e (m)/1 -> Sum3/1
  Sum3/1 -> Kp/1, Kp1/1

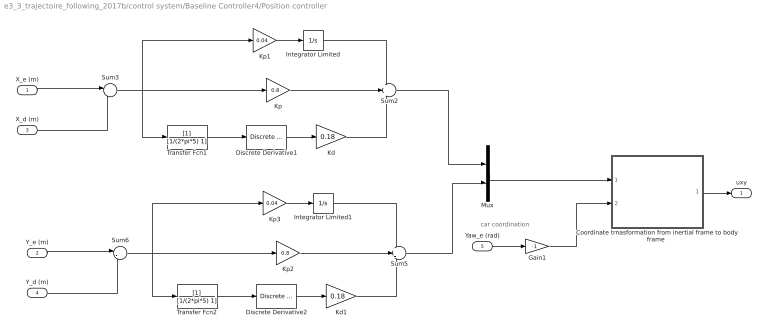
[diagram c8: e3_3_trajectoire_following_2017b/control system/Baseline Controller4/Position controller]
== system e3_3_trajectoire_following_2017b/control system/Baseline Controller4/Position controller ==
  note: car coordination
  X_e (m) : Inport
  Y_e (m) : Inport  Port=2
  X_d (m) : Inport  Port=3
  Y_d (m) : Inport  Port=4
  Yaw_e (rad) : Inport  Port=5
  "Coordinate trnasformation from inertial frame to body frame " : MATLAB Function  TreatAsAtomicUnit=on
  Discrete Derivative1 : simulink/Discrete/Discrete Derivative  gainval=1.0  ICPrevScaledInput=0.0  OutMin=[]  OutMax=[]  OutDataType=fixdt(1, 16)  OutScaling=2^-10  DoSatur=off
  Discrete Derivative2 : simulink/Discrete/Discrete Derivative  gainval=1.0  ICPrevScaledInput=0.0  OutMin=[]  OutMax=[]  OutDataType=fixdt(1, 16)  OutScaling=2^-10  DoSatur=off
  Gain1 : Gain  Gain=-1
  Integrator Limited : Integrator  LimitOutput=on  UpperSaturationLimit=0.5  LowerSaturationLimit=-0.5
  Integrator Limited1 : Integrator  LimitOutput=on  UpperSaturationLimit=0.5  LowerSaturationLimit=-0.5
  Kd : Gain  Gain=0.18
  Kd1 : Gain  Gain=0.18
  Kp : Gain  Gain=0.8
  Kp1 : Gain  Gain=0.04
  Kp2 : Gain  Gain=0.8
  Kp3 : Gain  Gain=0.04
  Mux : Mux  Inputs=2
  Sum2 : Sum  Inputs=+++
  Sum3 : Sum  Inputs=|-+
  Sum5 : Sum  Inputs=+++
  Sum6 : Sum  Inputs=|-+
  Transfer Fcn1 : TransferFcn  Denominator=[1/(2*pi*5) 1]
  Transfer Fcn2 : TransferFcn  Denominator=[1/(2*pi*5) 1]
  uxy : Outport  VectorParamsAs1DForOutWhenUnconnected=off
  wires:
  Sum6/1 -> Transfer Fcn2/1, Kp3/1, Kp2/1
  Discrete Derivative2/1 -> Kd1/1
  Kd1/1 -> Sum5/3
  Transfer Fcn2/1 -> Discrete Derivative2/1
  Y_d (m)/1 -> Sum6/2
  Transfer Fcn1/1 -> Discrete Derivative1/1
  Kd/1 -> Sum2/3
  Discrete Derivative1/1 -> Kd/1
  Sum3/1 -> Kp1/1, Transfer Fcn1/1, Kp/1
  X_d (m)/1 -> Sum3/2
  "Coordinate trnasformation from inertial frame to body frame "/1(Vec_xy) -> uxy/1
  Gain1/1 -> "Coordinate trnasformation from inertial frame to body frame "/2(psi)
  Mux/1 -> "Coordinate trnasformation from inertial frame to body frame "/1(Vec_i)
  Kp3/1 -> Integrator Limited1/1
  Sum5/1 -> Mux/2
  Integrator Limited1/1 -> Sum5/1
  Y_e (m)/1 -> Sum6/1
  Kp2/1 -> Sum5/2
  Kp/1 -> Sum2/2
  Kp1/1 -> Integrator Limited/1
  Sum2/1 -> Mux/1
  Integrator Limited/1 -> Sum2/1
  X_e (m)/1 -> Sum3/1
  Yaw_e (rad)/1 -> Gain1/1

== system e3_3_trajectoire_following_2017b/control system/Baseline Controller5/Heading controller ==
  yaw_e (rad) : Inport
  yaw_d. (rad) : Inport  Port=2
  Integrator Limited : Integrator  Commented=on  LimitOutput=on  UpperSaturationLimit=0.3  LowerSaturationLimit=-0.3
  Ki : Gain  Commented=on  Gain=0.01
  Sum1 : Sum  Inputs=|-+
  Sum2 : Sum  Inputs=|++
  proportional control gain - yaw : Gain  Gain=1.0
  yaw_rate_d. (rad/s) : Outport  VectorParamsAs1DForOutWhenUnconnected=off
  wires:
  Sum1/1 -> Ki/1, proportional control gain - yaw/1
  yaw_e (rad)/1 -> Sum1/1
  yaw_d. (rad)/1 -> Sum1/2
  proportional control gain - yaw/1 -> Sum2/1
  Integrator Limited/1 -> Sum2/2
  Ki/1 -> Integrator Limited/1
  Sum2/1 -> yaw_rate_d. (rad/s)/1

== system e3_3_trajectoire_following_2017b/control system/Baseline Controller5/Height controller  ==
  Z_d. (m) : Inport
  Z_e (m) : Inport  Port=2
  V_z : Inport  Port=3
  Integrator Limited : Integrator  LimitOutput=on  UpperSaturationLimit=0.5  LowerSaturationLimit=-0.5
  Kd : Gain  Gain=0.01
  Kp : Gain  Gain=1.0
  Kp1 : Gain  Gain=0.01
  Sum1 : Sum  Inputs=|-+
  Sum2 : Sum  Inputs=+++
  Sum3 : Sum  Inputs=|-+
  Transfer Fcn1 : TransferFcn  Denominator=[1/(2*pi*10) 1]
  Z_velocity_d (m/s) : Outport  VectorParamsAs1DForOutWhenUnconnected=off
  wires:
  Sum3/1 -> Kp1/1, Kp/1
  Z_e (m)/1 -> Sum3/1
  V_z/1 -> Transfer Fcn1/1
  Sum1/1 -> Kd/1
  Sum2/1 -> Z_velocity_d (m/s)/1
  Kp/1 -> Sum2/2
  Kd/1 -> Sum2/3
  Kp1/1 -> Integrator Limited/1
  Integrator Limited/1 -> Sum2/1
  Transfer Fcn1/1 -> Sum1/1
  Z_d. (m)/1 -> Sum3/2

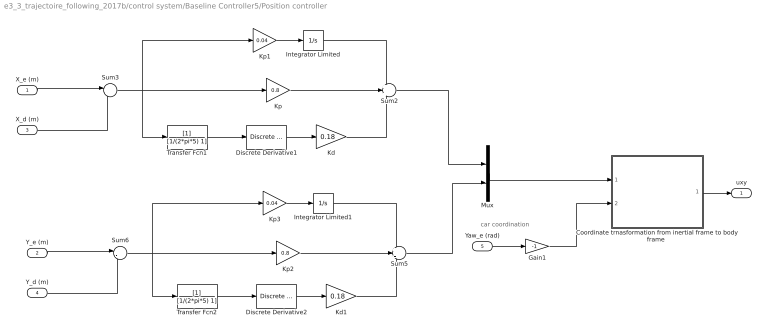
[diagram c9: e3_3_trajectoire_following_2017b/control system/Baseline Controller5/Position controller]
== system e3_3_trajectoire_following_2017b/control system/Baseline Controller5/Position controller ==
  note: car coordination
  X_e (m) : Inport
  Y_e (m) : Inport  Port=2
  X_d (m) : Inport  Port=3
  Y_d (m) : Inport  Port=4
  Yaw_e (rad) : Inport  Port=5
  "Coordinate trnasformation from inertial frame to body frame " : MATLAB Function  TreatAsAtomicUnit=on
  Discrete Derivative1 : simulink/Discrete/Discrete Derivative  gainval=1.0  ICPrevScaledInput=0.0  OutMin=[]  OutMax=[]  OutDataType=fixdt(1, 16)  OutScaling=2^-10  DoSatur=off
  Discrete Derivative2 : simulink/Discrete/Discrete Derivative  gainval=1.0  ICPrevScaledInput=0.0  OutMin=[]  OutMax=[]  OutDataType=fixdt(1, 16)  OutScaling=2^-10  DoSatur=off
  Gain1 : Gain  Gain=-1
  Integrator Limited : Integrator  LimitOutput=on  UpperSaturationLimit=0.5  LowerSaturationLimit=-0.5
  Integrator Limited1 : Integrator  LimitOutput=on  UpperSaturationLimit=0.5  LowerSaturationLimit=-0.5
  Kd : Gain  Gain=0.18
  Kd1 : Gain  Gain=0.18
  Kp : Gain  Gain=0.8
  Kp1 : Gain  Gain=0.04
  Kp2 : Gain  Gain=0.8
  Kp3 : Gain  Gain=0.04
  Mux : Mux  Inputs=2
  Sum2 : Sum  Inputs=+++
  Sum3 : Sum  Inputs=|-+
  Sum5 : Sum  Inputs=+++
  Sum6 : Sum  Inputs=|-+
  Transfer Fcn1 : TransferFcn  Denominator=[1/(2*pi*5) 1]
  Transfer Fcn2 : TransferFcn  Denominator=[1/(2*pi*5) 1]
  uxy : Outport  VectorParamsAs1DForOutWhenUnconnected=off
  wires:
  Yaw_e (rad)/1 -> Gain1/1
  X_e (m)/1 -> Sum3/1
  Integrator Limited/1 -> Sum2/1
  Sum2/1 -> Mux/1
  Kp1/1 -> Integrator Limited/1
  Kp/1 -> Sum2/2
  Kp2/1 -> Sum5/2
  Y_e (m)/1 -> Sum6/1
  Integrator Limited1/1 -> Sum5/1
  Sum5/1 -> Mux/2
  Kp3/1 -> Integrator Limited1/1
  Mux/1 -> "Coordinate trnasformation from inertial frame to body frame "/1(Vec_i)
  Gain1/1 -> "Coordinate trnasformation from inertial frame to body frame "/2(psi)
  "Coordinate trnasformation from inertial frame to body frame "/1(Vec_xy) -> uxy/1
  X_d (m)/1 -> Sum3/2
  Sum3/1 -> Kp/1, Transfer Fcn1/1, Kp1/1
  Discrete Derivative1/1 -> Kd/1
  Kd/1 -> Sum2/3
  Transfer Fcn1/1 -> Discrete Derivative1/1
  Y_d (m)/1 -> Sum6/2
  Transfer Fcn2/1 -> Discrete Derivative2/1
  Kd1/1 -> Sum5/3
  Discrete Derivative2/1 -> Kd1/1
  Sum6/1 -> Kp2/1, Kp3/1, Transfer Fcn2/1

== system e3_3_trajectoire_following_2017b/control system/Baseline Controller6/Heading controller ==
  yaw_e (rad) : Inport
  yaw_d. (rad) : Inport  Port=2
  Integrator Limited : Integrator  Commented=on  LimitOutput=on  UpperSaturationLimit=0.3  LowerSaturationLimit=-0.3
  Ki : Gain  Commented=on  Gain=0.01
  Sum1 : Sum  Inputs=|-+
  Sum2 : Sum  Inputs=|++
  proportional control gain - yaw : Gain  Gain=1.0
  yaw_rate_d. (rad/s) : Outport  VectorParamsAs1DForOutWhenUnconnected=off
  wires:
  Sum2/1 -> yaw_rate_d. (rad/s)/1
  Ki/1 -> Integrator Limited/1
  Integrator Limited/1 -> Sum2/2
  proportional control gain - yaw/1 -> Sum2/1
  yaw_d. (rad)/1 -> Sum1/2
  yaw_e (rad)/1 -> Sum1/1
  Sum1/1 -> proportional control gain - yaw/1, Ki/1

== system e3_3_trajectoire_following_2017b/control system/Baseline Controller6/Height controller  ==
  Z_d. (m) : Inport
  Z_e (m) : Inport  Port=2
  V_z : Inport  Port=3
  Integrator Limited : Integrator  LimitOutput=on  UpperSaturationLimit=0.5  LowerSaturationLimit=-0.5
  Kd : Gain  Gain=0.01
  Kp : Gain  Gain=1.0
  Kp1 : Gain  Gain=0.01
  Sum1 : Sum  Inputs=|-+
  Sum2 : Sum  Inputs=+++
  Sum3 : Sum  Inputs=|-+
  Transfer Fcn1 : TransferFcn  Denominator=[1/(2*pi*10) 1]
  Z_velocity_d (m/s) : Outport  VectorParamsAs1DForOutWhenUnconnected=off
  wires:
  Z_d. (m)/1 -> Sum3/2
  Transfer Fcn1/1 -> Sum1/1
  Integrator Limited/1 -> Sum2/1
  Kp1/1 -> Integrator Limited/1
  Kd/1 -> Sum2/3
  Kp/1 -> Sum2/2
  Sum2/1 -> Z_velocity_d (m/s)/1
  Sum1/1 -> Kd/1
  V_z/1 -> Transfer Fcn1/1
  Z_e (m)/1 -> Sum3/1
  Sum3/1 -> Kp/1, Kp1/1

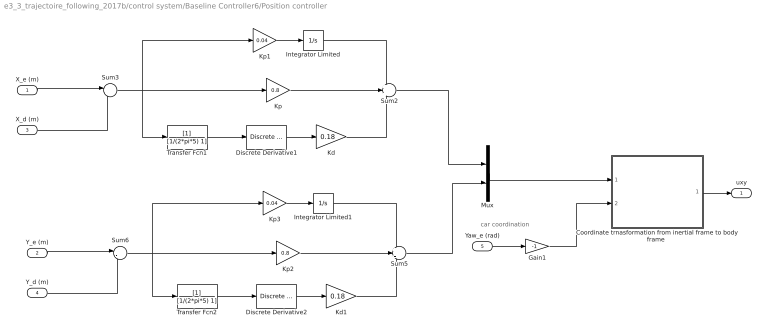
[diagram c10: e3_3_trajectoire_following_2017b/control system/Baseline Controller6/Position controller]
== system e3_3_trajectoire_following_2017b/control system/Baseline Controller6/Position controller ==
  note: car coordination
  X_e (m) : Inport
  Y_e (m) : Inport  Port=2
  X_d (m) : Inport  Port=3
  Y_d (m) : Inport  Port=4
  Yaw_e (rad) : Inport  Port=5
  "Coordinate trnasformation from inertial frame to body frame " : MATLAB Function  TreatAsAtomicUnit=on
  Discrete Derivative1 : simulink/Discrete/Discrete Derivative  gainval=1.0  ICPrevScaledInput=0.0  OutMin=[]  OutMax=[]  OutDataType=fixdt(1, 16)  OutScaling=2^-10  DoSatur=off
  Discrete Derivative2 : simulink/Discrete/Discrete Derivative  gainval=1.0  ICPrevScaledInput=0.0  OutMin=[]  OutMax=[]  OutDataType=fixdt(1, 16)  OutScaling=2^-10  DoSatur=off
  Gain1 : Gain  Gain=-1
  Integrator Limited : Integrator  LimitOutput=on  UpperSaturationLimit=0.5  LowerSaturationLimit=-0.5
  Integrator Limited1 : Integrator  LimitOutput=on  UpperSaturationLimit=0.5  LowerSaturationLimit=-0.5
  Kd : Gain  Gain=0.18
  Kd1 : Gain  Gain=0.18
  Kp : Gain  Gain=0.8
  Kp1 : Gain  Gain=0.04
  Kp2 : Gain  Gain=0.8
  Kp3 : Gain  Gain=0.04
  Mux : Mux  Inputs=2
  Sum2 : Sum  Inputs=+++
  Sum3 : Sum  Inputs=|-+
  Sum5 : Sum  Inputs=+++
  Sum6 : Sum  Inputs=|-+
  Transfer Fcn1 : TransferFcn  Denominator=[1/(2*pi*5) 1]
  Transfer Fcn2 : TransferFcn  Denominator=[1/(2*pi*5) 1]
  uxy : Outport  VectorParamsAs1DForOutWhenUnconnected=off
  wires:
  Sum6/1 -> Transfer Fcn2/1, Kp3/1, Kp2/1
  Discrete Derivative2/1 -> Kd1/1
  Kd1/1 -> Sum5/3
  Transfer Fcn2/1 -> Discrete Derivative2/1
  Y_d (m)/1 -> Sum6/2
  Transfer Fcn1/1 -> Discrete Derivative1/1
  Kd/1 -> Sum2/3
  Discrete Derivative1/1 -> Kd/1
  Sum3/1 -> Kp1/1, Transfer Fcn1/1, Kp/1
  X_d (m)/1 -> Sum3/2
  "Coordinate trnasformation from inertial frame to body frame "/1(Vec_xy) -> uxy/1
  Gain1/1 -> "Coordinate trnasformation from inertial frame to body frame "/2(psi)
  Mux/1 -> "Coordinate trnasformation from inertial frame to body frame "/1(Vec_i)
  Kp3/1 -> Integrator Limited1/1
  Sum5/1 -> Mux/2
  Integrator Limited1/1 -> Sum5/1
  Y_e (m)/1 -> Sum6/1
  Kp2/1 -> Sum5/2
  Kp/1 -> Sum2/2
  Kp1/1 -> Integrator Limited/1
  Sum2/1 -> Mux/1
  Integrator Limited/1 -> Sum2/1
  X_e (m)/1 -> Sum3/1
  Yaw_e (rad)/1 -> Gain1/1

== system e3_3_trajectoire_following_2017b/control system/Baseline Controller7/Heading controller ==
  yaw_e (rad) : Inport
  yaw_d. (rad) : Inport  Port=2
  Integrator Limited : Integrator  Commented=on  LimitOutput=on  UpperSaturationLimit=0.3  LowerSaturationLimit=-0.3
  Ki : Gain  Commented=on  Gain=0.01
  Sum1 : Sum  Inputs=|-+
  Sum2 : Sum  Inputs=|++
  proportional control gain - yaw : Gain  Gain=1.0
  yaw_rate_d. (rad/s) : Outport  VectorParamsAs1DForOutWhenUnconnected=off
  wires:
  Sum1/1 -> Ki/1, proportional control gain - yaw/1
  yaw_e (rad)/1 -> Sum1/1
  yaw_d. (rad)/1 -> Sum1/2
  proportional control gain - yaw/1 -> Sum2/1
  Integrator Limited/1 -> Sum2/2
  Ki/1 -> Integrator Limited/1
  Sum2/1 -> yaw_rate_d. (rad/s)/1

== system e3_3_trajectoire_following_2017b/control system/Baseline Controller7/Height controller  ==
  Z_d. (m) : Inport
  Z_e (m) : Inport  Port=2
  V_z : Inport  Port=3
  Integrator Limited : Integrator  LimitOutput=on  UpperSaturationLimit=0.5  LowerSaturationLimit=-0.5
  Kd : Gain  Gain=0.01
  Kp : Gain  Gain=1.0
  Kp1 : Gain  Gain=0.01
  Sum1 : Sum  Inputs=|-+
  Sum2 : Sum  Inputs=+++
  Sum3 : Sum  Inputs=|-+
  Transfer Fcn1 : TransferFcn  Denominator=[1/(2*pi*10) 1]
  Z_velocity_d (m/s) : Outport  VectorParamsAs1DForOutWhenUnconnected=off
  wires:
  Sum3/1 -> Kp1/1, Kp/1
  Z_e (m)/1 -> Sum3/1
  V_z/1 -> Transfer Fcn1/1
  Sum1/1 -> Kd/1
  Sum2/1 -> Z_velocity_d (m/s)/1
  Kp/1 -> Sum2/2
  Kd/1 -> Sum2/3
  Kp1/1 -> Integrator Limited/1
  Integrator Limited/1 -> Sum2/1
  Transfer Fcn1/1 -> Sum1/1
  Z_d. (m)/1 -> Sum3/2

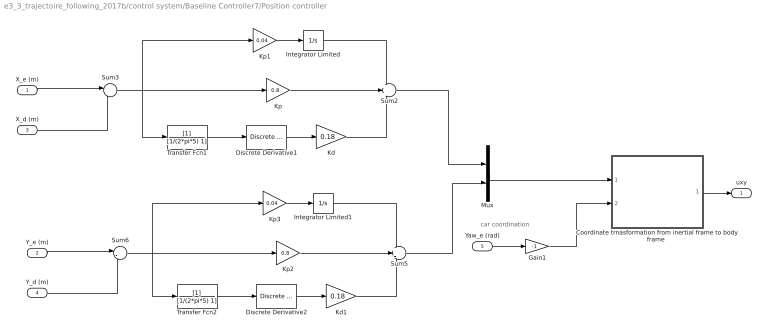
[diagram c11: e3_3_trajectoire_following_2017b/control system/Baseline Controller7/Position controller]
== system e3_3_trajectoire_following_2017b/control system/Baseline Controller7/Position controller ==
  note: car coordination
  X_e (m) : Inport
  Y_e (m) : Inport  Port=2
  X_d (m) : Inport  Port=3
  Y_d (m) : Inport  Port=4
  Yaw_e (rad) : Inport  Port=5
  "Coordinate trnasformation from inertial frame to body frame " : MATLAB Function  TreatAsAtomicUnit=on
  Discrete Derivative1 : simulink/Discrete/Discrete Derivative  gainval=1.0  ICPrevScaledInput=0.0  OutMin=[]  OutMax=[]  OutDataType=fixdt(1, 16)  OutScaling=2^-10  DoSatur=off
  Discrete Derivative2 : simulink/Discrete/Discrete Derivative  gainval=1.0  ICPrevScaledInput=0.0  OutMin=[]  OutMax=[]  OutDataType=fixdt(1, 16)  OutScaling=2^-10  DoSatur=off
  Gain1 : Gain  Gain=-1
  Integrator Limited : Integrator  LimitOutput=on  UpperSaturationLimit=0.5  LowerSaturationLimit=-0.5
  Integrator Limited1 : Integrator  LimitOutput=on  UpperSaturationLimit=0.5  LowerSaturationLimit=-0.5
  Kd : Gain  Gain=0.18
  Kd1 : Gain  Gain=0.18
  Kp : Gain  Gain=0.8
  Kp1 : Gain  Gain=0.04
  Kp2 : Gain  Gain=0.8
  Kp3 : Gain  Gain=0.04
  Mux : Mux  Inputs=2
  Sum2 : Sum  Inputs=+++
  Sum3 : Sum  Inputs=|-+
  Sum5 : Sum  Inputs=+++
  Sum6 : Sum  Inputs=|-+
  Transfer Fcn1 : TransferFcn  Denominator=[1/(2*pi*5) 1]
  Transfer Fcn2 : TransferFcn  Denominator=[1/(2*pi*5) 1]
  uxy : Outport  VectorParamsAs1DForOutWhenUnconnected=off
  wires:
  Yaw_e (rad)/1 -> Gain1/1
  X_e (m)/1 -> Sum3/1
  Integrator Limited/1 -> Sum2/1
  Sum2/1 -> Mux/1
  Kp1/1 -> Integrator Limited/1
  Kp/1 -> Sum2/2
  Kp2/1 -> Sum5/2
  Y_e (m)/1 -> Sum6/1
  Integrator Limited1/1 -> Sum5/1
  Sum5/1 -> Mux/2
  Kp3/1 -> Integrator Limited1/1
  Mux/1 -> "Coordinate trnasformation from inertial frame to body frame "/1(Vec_i)
  Gain1/1 -> "Coordinate trnasformation from inertial frame to body frame "/2(psi)
  "Coordinate trnasformation from inertial frame to body frame "/1(Vec_xy) -> uxy/1
  X_d (m)/1 -> Sum3/2
  Sum3/1 -> Kp/1, Transfer Fcn1/1, Kp1/1
  Discrete Derivative1/1 -> Kd/1
  Kd/1 -> Sum2/3
  Transfer Fcn1/1 -> Discrete Derivative1/1
  Y_d (m)/1 -> Sum6/2
  Transfer Fcn2/1 -> Discrete Derivative2/1
  Kd1/1 -> Sum5/3
  Discrete Derivative2/1 -> Kd1/1
  Sum6/1 -> Kp2/1, Kp3/1, Transfer Fcn2/1

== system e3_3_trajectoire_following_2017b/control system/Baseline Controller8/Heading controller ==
  yaw_e (rad) : Inport
  yaw_d. (rad) : Inport  Port=2
  Integrator Limited : Integrator  Commented=on  LimitOutput=on  UpperSaturationLimit=0.3  LowerSaturationLimit=-0.3
  Ki : Gain  Commented=on  Gain=0.01
  Sum1 : Sum  Inputs=|-+
  Sum2 : Sum  Inputs=|++
  proportional control gain - yaw : Gain  Gain=1.0
  yaw_rate_d. (rad/s) : Outport  VectorParamsAs1DForOutWhenUnconnected=off
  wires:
  Sum2/1 -> yaw_rate_d. (rad/s)/1
  Ki/1 -> Integrator Limited/1
  Integrator Limited/1 -> Sum2/2
  proportional control gain - yaw/1 -> Sum2/1
  yaw_d. (rad)/1 -> Sum1/2
  yaw_e (rad)/1 -> Sum1/1
  Sum1/1 -> proportional control gain - yaw/1, Ki/1

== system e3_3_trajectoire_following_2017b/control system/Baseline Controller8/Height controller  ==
  Z_d. (m) : Inport
  Z_e (m) : Inport  Port=2
  V_z : Inport  Port=3
  Integrator Limited : Integrator  LimitOutput=on  UpperSaturationLimit=0.5  LowerSaturationLimit=-0.5
  Kd : Gain  Gain=0.01
  Kp : Gain  Gain=1.0
  Kp1 : Gain  Gain=0.01
  Sum1 : Sum  Inputs=|-+
  Sum2 : Sum  Inputs=+++
  Sum3 : Sum  Inputs=|-+
  Transfer Fcn1 : TransferFcn  Denominator=[1/(2*pi*10) 1]
  Z_velocity_d (m/s) : Outport  VectorParamsAs1DForOutWhenUnconnected=off
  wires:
  Z_d. (m)/1 -> Sum3/2
  Transfer Fcn1/1 -> Sum1/1
  Integrator Limited/1 -> Sum2/1
  Kp1/1 -> Integrator Limited/1
  Kd/1 -> Sum2/3
  Kp/1 -> Sum2/2
  Sum2/1 -> Z_velocity_d (m/s)/1
  Sum1/1 -> Kd/1
  V_z/1 -> Transfer Fcn1/1
  Z_e (m)/1 -> Sum3/1
  Sum3/1 -> Kp/1, Kp1/1

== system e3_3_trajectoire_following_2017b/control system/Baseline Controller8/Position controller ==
  note: car coordination
  X_e (m) : Inport
  Y_e (m) : Inport  Port=2
  X_d (m) : Inport  Port=3
  Y_d (m) : Inport  Port=4
  Yaw_e (rad) : Inport  Port=5
  "Coordinate trnasformation from inertial frame to body frame " : MATLAB Function  TreatAsAtomicUnit=on
  Discrete Derivative1 : simulink/Discrete/Discrete Derivative  gainval=1.0  ICPrevScaledInput=0.0  OutMin=[]  OutMax=[]  OutDataType=fixdt(1, 16)  OutScaling=2^-10  DoSatur=off
  Discrete Derivative2 : simulink/Discrete/Discrete Derivative  gainval=1.0  ICPrevScaledInput=0.0  OutMin=[]  OutMax=[]  OutDataType=fixdt(1, 16)  OutScaling=2^-10  DoSatur=off
  Gain1 : Gain  Gain=-1
  Integrator Limited : Integrator  LimitOutput=on  UpperSaturationLimit=0.5  LowerSaturationLimit=-0.5
  Integrator Limited1 : Integrator  LimitOutput=on  UpperSaturationLimit=0.5  LowerSaturationLimit=-0.5
  Kd : Gain  Gain=0.18
  Kd1 : Gain  Gain=0.18
  Kp : Gain  Gain=0.8
  Kp1 : Gain  Gain=0.04
  Kp2 : Gain  Gain=0.8
  Kp3 : Gain  Gain=0.04
  Mux : Mux  Inputs=2
  Sum2 : Sum  Inputs=+++
  Sum3 : Sum  Inputs=|-+
  Sum5 : Sum  Inputs=+++
  Sum6 : Sum  Inputs=|-+
  Transfer Fcn1 : TransferFcn  Denominator=[1/(2*pi*5) 1]
  Transfer Fcn2 : TransferFcn  Denominator=[1/(2*pi*5) 1]
  uxy : Outport  VectorParamsAs1DForOutWhenUnconnected=off
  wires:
  Sum6/1 -> Transfer Fcn2/1, Kp3/1, Kp2/1
  Discrete Derivative2/1 -> Kd1/1
  Kd1/1 -> Sum5/3
  Transfer Fcn2/1 -> Discrete Derivative2/1
  Y_d (m)/1 -> Sum6/2
  Transfer Fcn1/1 -> Discrete Derivative1/1
  Kd/1 -> Sum2/3
  Discrete Derivative1/1 -> Kd/1
  Sum3/1 -> Kp1/1, Transfer Fcn1/1, Kp/1
  X_d (m)/1 -> Sum3/2
  "Coordinate trnasformation from inertial frame to body frame "/1(Vec_xy) -> uxy/1
  Gain1/1 -> "Coordinate trnasformation from inertial frame to body frame "/2(psi)
  Mux/1 -> "Coordinate trnasformation from inertial frame to body frame "/1(Vec_i)
  Kp3/1 -> Integrator Limited1/1
  Sum5/1 -> Mux/2
  Integrator Limited1/1 -> Sum5/1
  Y_e (m)/1 -> Sum6/1
  Kp2/1 -> Sum5/2
  Kp/1 -> Sum2/2
  Kp1/1 -> Integrator Limited/1
  Sum2/1 -> Mux/1
  Integrator Limited/1 -> Sum2/1
  X_e (m)/1 -> Sum3/1
  Yaw_e (rad)/1 -> Gain1/1

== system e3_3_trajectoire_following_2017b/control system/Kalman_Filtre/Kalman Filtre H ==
  The system output: Position : Inport
  real_vz : Inport  Port=2
  Demux : Demux  Outputs=9
  Error : Scope
  Kalman Filtre H : Subsystem
  Kalman Filtre for getting the velocity H : MATLAB Function  TreatAsAtomicUnit=on
  Manual Switch1 : ManualSwitch  CurrentSetting=0
  Memory block for resolving the 'algebraic loop' problem : Memory
  Scope2 : Scope
  Scope4 : Scope  NumInputPorts=8
  Sum : Sum  Inputs=-+|
  The comparison of velocity signal between 'Derivative' and 'Kalman filtering' : Scope  NumInputPorts=2
  Unit Delay1 : UnitDelay  SampleTime=-1  HasFrameUpgradeWarning=on
  Unit Delay7 : UnitDelay  SampleTime=-1  HasFrameUpgradeWarning=on
  Unit Delay8 : UnitDelay  SampleTime=-1  HasFrameUpgradeWarning=on
  Zero-Order Hold1 : ZeroOrderHold  SampleTime=-1
  Out velocity feedback : Outport  VectorParamsAs1DForOutWhenUnconnected=off
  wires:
  Kalman Filtre for getting the velocity H/1(Covariance_matrice) -> Scope2/1
  Kalman Filtre for getting the velocity H/2(X_Kalmanfiltred) -> Memory block for resolving the 'algebraic loop' problem/1
  Memory block for resolving the 'algebraic loop' problem/1 -> Demux/1
  Zero-Order Hold1/1 -> Kalman Filtre for getting the velocity H/1(Mesurement_Velocity)
  Manual Switch1/1 -> Out velocity feedback/1
  Demux/1 -> Scope4/1
  The system output: Position/1 -> Kalman Filtre H/1(The system output: Position), Unit Delay7/1
  Demux/2 -> Scope4/2
  Demux/3 -> Scope4/3
  Demux/4 -> Scope4/4
  Demux/5 -> Scope4/5
  Unit Delay8/1 -> Zero-Order Hold1/1
  Demux/6 -> Scope4/6
  Demux/7 -> Scope4/8
  Demux/8 -> Manual Switch1/1, Sum/1, The comparison of velocity signal between 'Derivative' and 'Kalman filtering'/1
  Demux/9 -> Scope4/7
  real_vz/1 -> Manual Switch1/2, The comparison of velocity signal between 'Derivative' and 'Kalman filtering'/2
  Unit Delay7/1 -> Unit Delay1/1
  Unit Delay1/1 -> Unit Delay8/1
  Sum/1 -> Error/1
  Kalman Filtre H/1(Out velocity feedback) -> Sum/2

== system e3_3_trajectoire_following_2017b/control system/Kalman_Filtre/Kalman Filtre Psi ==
  The system output: Position : Inport
  real_vpsi : Inport  Port=2
  Demux : Demux  Outputs=9
  Error : Scope
  Kalman Filtre Psi : Subsystem
  Kalman Filtre for getting the velocity Psi : MATLAB Function  TreatAsAtomicUnit=on
  Manual Switch1 : ManualSwitch  CurrentSetting=0
  Memory block for resolving the 'algebraic loop' problem : Memory
  Scope2 : Scope
  Scope4 : Scope  NumInputPorts=8
  Sum : Sum  Inputs=-+|
  The comparison of velocity signal between 'Derivative' and 'Kalman filtering' : Scope  NumInputPorts=2
  Unit Delay1 : UnitDelay  SampleTime=-1  HasFrameUpgradeWarning=on
  Unit Delay7 : UnitDelay  SampleTime=-1  HasFrameUpgradeWarning=on
  Unit Delay8 : UnitDelay  SampleTime=-1  HasFrameUpgradeWarning=on
  Zero-Order Hold1 : ZeroOrderHold  SampleTime=-1
  Out velocity feedback : Outport  VectorParamsAs1DForOutWhenUnconnected=off
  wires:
  Kalman Filtre for getting the velocity Psi/1(Covariance_matrice) -> Scope2/1
  Kalman Filtre for getting the velocity Psi/2(X_Kalmanfiltred) -> Memory block for resolving the 'algebraic loop' problem/1
  Memory block for resolving the 'algebraic loop' problem/1 -> Demux/1
  Zero-Order Hold1/1 -> Kalman Filtre for getting the velocity Psi/1(Mesurement_Velocity)
  Manual Switch1/1 -> Out velocity feedback/1
  Demux/1 -> Scope4/1
  The system output: Position/1 -> Kalman Filtre Psi/1(The system output: Position), Unit Delay7/1
  Demux/2 -> Scope4/2
  Demux/3 -> Scope4/3
  Demux/4 -> Scope4/4
  Demux/5 -> Scope4/5
  Unit Delay8/1 -> Zero-Order Hold1/1
  Demux/6 -> Scope4/6
  Demux/7 -> Scope4/8
  Demux/8 -> Manual Switch1/1, Sum/1, The comparison of velocity signal between 'Derivative' and 'Kalman filtering'/1
  Demux/9 -> Scope4/7
  real_vpsi/1 -> Manual Switch1/2, The comparison of velocity signal between 'Derivative' and 'Kalman filtering'/2
  Unit Delay7/1 -> Unit Delay1/1
  Unit Delay1/1 -> Unit Delay8/1
  Sum/1 -> Error/1
  Kalman Filtre Psi/1(Out velocity feedback) -> Sum/2

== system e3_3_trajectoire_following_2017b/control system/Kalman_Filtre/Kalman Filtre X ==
  The system output: Position : Inport
  real_vx : Inport  Port=2
  Demux : Demux  Outputs=9
  Error : Scope
  Kalman Filtre X : Subsystem
  Kalman Filtre for getting the velocity X : MATLAB Function  TreatAsAtomicUnit=on
  Manual Switch1 : ManualSwitch  CurrentSetting=0
  Memory block for resolving the 'algebraic loop' problem : Memory
  Scope : Scope
  Scope4 : Scope  NumInputPorts=8
  Sum : Sum  Inputs=-+|
  The comparison of velocity signal between 'Derivative' and 'Kalman filtering' : Scope  NumInputPorts=3
  Unit Delay{1..2,7..8} (4 alike) : UnitDelay  SampleTime=-1  HasFrameUpgradeWarning=on
  Zero-Order Hold1 : ZeroOrderHold  SampleTime=-1
  Out velocity feedback : Outport  VectorParamsAs1DForOutWhenUnconnected=off
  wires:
  Kalman Filtre for getting the velocity X/1(Covariance_matrice) -> Scope/1
  Kalman Filtre for getting the velocity X/2(X_Kalmanfiltred) -> Memory block for resolving the 'algebraic loop' problem/1
  Memory block for resolving the 'algebraic loop' problem/1 -> Demux/1
  Zero-Order Hold1/1 -> Kalman Filtre for getting the velocity X/1(Mesurement_Velocity)
  Manual Switch1/1 -> Out velocity feedback/1
  Demux/1 -> Scope4/1
  The system output: Position/1 -> Kalman Filtre X/1(The system output: Position), Unit Delay7/1
  Demux/2 -> Scope4/2
  Demux/3 -> Scope4/3
  Demux/4 -> Scope4/4
  Demux/5 -> Scope4/5
  Unit Delay7/1 -> Unit Delay8/1
  Unit Delay8/1 -> Unit Delay1/1
  Demux/6 -> Scope4/6
  Demux/7 -> Scope4/8
  Demux/8 -> Manual Switch1/1, Sum/1, The comparison of velocity signal between 'Derivative' and 'Kalman filtering'/1
  Demux/9 -> Scope4/7
  real_vx/1 -> Manual Switch1/2, The comparison of velocity signal between 'Derivative' and 'Kalman filtering'/2
  Unit Delay1/1 -> Unit Delay2/1
  Unit Delay2/1 -> Zero-Order Hold1/1
  Kalman Filtre X/1(Out velocity feedback) -> The comparison of velocity signal between 'Derivative' and 'Kalman filtering'/3, Sum/2
  Sum/1 -> Error/1

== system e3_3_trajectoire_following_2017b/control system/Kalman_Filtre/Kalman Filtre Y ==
  The system output: Position : Inport
  real_vy : Inport  Port=2
  Demux : Demux  Outputs=9
  Error : Scope
  Kalman Filtre Y : Subsystem
  Kalman Filtre for getting the velocity Y : MATLAB Function  TreatAsAtomicUnit=on
  Manual Switch1 : ManualSwitch  CurrentSetting=0
  Memory block for resolving the 'algebraic loop' problem : Memory
  Scope2 : Scope
  Scope4 : Scope  NumInputPorts=8
  Sum : Sum  Inputs=-+|
  The comparison of velocity signal between 'Derivative' and 'Kalman filtering' : Scope  NumInputPorts=3
  Unit Delay{1..2,7..8} (4 alike) : UnitDelay  SampleTime=-1  HasFrameUpgradeWarning=on
  Zero-Order Hold1 : ZeroOrderHold  SampleTime=-1
  Out velocity feedback : Outport  VectorParamsAs1DForOutWhenUnconnected=off
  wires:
  Kalman Filtre for getting the velocity Y/1(Covariance_matrice) -> Scope2/1
  Kalman Filtre for getting the velocity Y/2(X_Kalmanfiltred) -> Memory block for resolving the 'algebraic loop' problem/1
  Memory block for resolving the 'algebraic loop' problem/1 -> Demux/1
  Zero-Order Hold1/1 -> Kalman Filtre for getting the velocity Y/1(Mesurement_Velocity)
  Manual Switch1/1 -> Out velocity feedback/1
  Demux/1 -> Scope4/1
  The system output: Position/1 -> Kalman Filtre Y/1(The system output: Position), Unit Delay7/1
  Demux/2 -> Scope4/2
  Demux/3 -> Scope4/3
  Demux/4 -> Scope4/4
  Demux/5 -> Scope4/5
  Unit Delay2/1 -> Zero-Order Hold1/1
  Demux/6 -> Scope4/6
  Demux/7 -> Scope4/8
  Demux/8 -> Manual Switch1/1, Sum/1, The comparison of velocity signal between 'Derivative' and 'Kalman filtering'/1
  Demux/9 -> Scope4/7
  real_vy/1 -> Manual Switch1/2, The comparison of velocity signal between 'Derivative' and 'Kalman filtering'/2
  Unit Delay1/1 -> Unit Delay2/1
  Unit Delay8/1 -> Unit Delay1/1
  Unit Delay7/1 -> Unit Delay8/1
  Sum/1 -> Error/1
  Kalman Filtre Y/1(Out velocity feedback) -> The comparison of velocity signal between 'Derivative' and 'Kalman filtering'/3, Sum/2

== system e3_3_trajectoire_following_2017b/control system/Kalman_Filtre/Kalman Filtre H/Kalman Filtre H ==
  The system output: Position : Inport
  Demux : Demux  Outputs=3
  Kalman Filtre for getting the velocity H : MATLAB Function  TreatAsAtomicUnit=on
  Memory block for resolving the 'algebraic loop' problem : Memory
  Scope2 : Scope
  Scope4 : Scope  NumInputPorts=2
  Out velocity feedback : Outport  VectorParamsAs1DForOutWhenUnconnected=off
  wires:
  Demux/2 -> Out velocity feedback/1
  Memory block for resolving the 'algebraic loop' problem/1 -> Demux/1
  Kalman Filtre for getting the velocity H/1(Covariance_matrice) -> Scope2/1
  The system output: Position/1 -> Kalman Filtre for getting the velocity H/1(Mesurement_Velocity)
  Demux/1 -> Scope4/1
  Kalman Filtre for getting the velocity H/2(X_Kalmanfiltred) -> Memory block for resolving the 'algebraic loop' problem/1
  Demux/3 -> Scope4/2

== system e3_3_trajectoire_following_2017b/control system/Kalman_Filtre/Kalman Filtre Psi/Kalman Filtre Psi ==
  The system output: Position : Inport
  Demux : Demux  Outputs=3
  Kalman Filtre for getting the velocity Psi : MATLAB Function  TreatAsAtomicUnit=on
  Memory block for resolving the 'algebraic loop' problem : Memory
  Scope1 : Scope  NumInputPorts=2
  Scope2 : Scope
  Out velocity feedback : Outport  VectorParamsAs1DForOutWhenUnconnected=off
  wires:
  Demux/2 -> Out velocity feedback/1
  Kalman Filtre for getting the velocity Psi/1(Covariance_matrice) -> Scope2/1
  The system output: Position/1 -> Kalman Filtre for getting the velocity Psi/1(Mesurement_Velocity)
  Demux/1 -> Scope1/1
  Demux/3 -> Scope1/2
  Kalman Filtre for getting the velocity Psi/2(X_Kalmanfiltred) -> Memory block for resolving the 'algebraic loop' problem/1
  Memory block for resolving the 'algebraic loop' problem/1 -> Demux/1

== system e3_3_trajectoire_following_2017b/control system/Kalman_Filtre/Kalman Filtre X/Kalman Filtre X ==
  The system output: Position : Inport
  Demux : Demux  Outputs=3
  Kalman Filtre for getting the velocity X : MATLAB Function  TreatAsAtomicUnit=on
  Memory block for resolving the 'algebraic loop' problem : Memory
  Scope2 : Scope
  Scope4 : Scope  NumInputPorts=2
  Out velocity feedback : Outport  VectorParamsAs1DForOutWhenUnconnected=off
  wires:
  Kalman Filtre for getting the velocity X/1(Covariance_matrice) -> Scope2/1
  Kalman Filtre for getting the velocity X/2(X_Kalmanfiltred) -> Memory block for resolving the 'algebraic loop' problem/1
  Memory block for resolving the 'algebraic loop' problem/1 -> Demux/1
  The system output: Position/1 -> Kalman Filtre for getting the velocity X/1(Mesurement_Velocity)
  Demux/2 -> Out velocity feedback/1
  Demux/1 -> Scope4/2
  Demux/3 -> Scope4/1

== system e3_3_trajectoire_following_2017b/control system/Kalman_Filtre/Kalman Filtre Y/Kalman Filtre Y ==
  The system output: Position : Inport
  Demux : Demux  Outputs=3
  Kalman Filtre for getting the velocity Y : MATLAB Function  TreatAsAtomicUnit=on
  Memory block for resolving the 'algebraic loop' problem : Memory
  Scope2 : Scope
  Scope4 : Scope  NumInputPorts=2
  Out velocity feedback : Outport  VectorParamsAs1DForOutWhenUnconnected=off
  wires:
  Kalman Filtre for getting the velocity Y/2(X_Kalmanfiltred) -> Memory block for resolving the 'algebraic loop' problem/1
  Demux/2 -> Out velocity feedback/1
  Kalman Filtre for getting the velocity Y/1(Covariance_matrice) -> Scope2/1
  Memory block for resolving the 'algebraic loop' problem/1 -> Demux/1
  The system output: Position/1 -> Kalman Filtre for getting the velocity Y/1(Mesurement_Velocity)
  Demux/1 -> Scope4/1
  Demux/3 -> Scope4/2

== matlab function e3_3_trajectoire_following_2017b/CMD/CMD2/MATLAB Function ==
function [x_d_, y_d_, z_d_] = fcn(x_d, y_d, z_d, timestamp, x,y,z,battery_status, sim_time_end,battery_threshold, z_d_for_land, UAV_NUM)
persistent s_x s_y s_z ready_land
if isempty(s_x)
    s_x = x;
end
if isempty(s_y)
    s_y = y;
end
if isempty(s_z)
    s_z = z;
end
if isempty(ready_land)
    ready_land = false;
end
    
battery_low = false;
for i = 1:UAV_NUM
    if battery_status(i) < battery_threshold
        battery_low = true;
        break;
    end
end
if sim_time_end - timestamp < 1
    tello_stop = true;
else
    tello_stop = false;
end
if battery_low || tello_stop
    if ~ready_land
        s_x = x;
        s_y = y;
        ready_land = true;
    end
    z_d_ = z_d_for_land;
    x_d_ = s_x;
    y_d_ = s_y;
else
   ready_land = false;
   s_x = x;
   s_y = y;
   x_d_ = x_d;
   y_d_ = y_d;
   z_d_ = z_d;
end

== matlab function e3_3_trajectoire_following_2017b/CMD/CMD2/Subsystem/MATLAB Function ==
function [x2_, y2_, z2_] = fcn(timestamp, sim_end_time, a, b, k, bb, w1, w2,tb2, tb3, tb4)
persistent time_start;
if isempty(time_start)
     time_start = timestamp;
end

if (timestamp - time_start) < 2
    t = 0;
elseif (sim_end_time - timestamp) >=2
    t = timestamp - 2;
else
    t = sim_end_time - 4;
end
    x2_ = a*sin(w1*(t - tb2));
    y2_ = b*cos(w2*(t - tb2));
    z2_ = k*y2_+bb;

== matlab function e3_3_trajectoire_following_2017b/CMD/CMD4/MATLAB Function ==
function [x_d_, y_d_, z_d_] = fcn(x_d, y_d, z_d, timestamp, x,y,z,battery_status, sim_time_end,battery_threshold, z_d_for_land, UAV_NUM)
persistent s_x s_y s_z ready_land
if isempty(s_x)
    s_x = x;
end
if isempty(s_y)
    s_y = y;
end
if isempty(s_z)
    s_z = z;
end
if isempty(ready_land)
    ready_land = false;
end
    
battery_low = false;
for i = 1:UAV_NUM
    if battery_status(i) < battery_threshold
        battery_low = true;
        break;
    end
end
if sim_time_end - timestamp < 1
    tello_stop = true;
else
    tello_stop = false;
end
if battery_low || tello_stop
    if ~ready_land
        s_x = x;
        s_y = y;
        ready_land = true;
    end
    z_d_ = z_d_for_land;
    x_d_ = s_x;
    y_d_ = s_y;
else
   ready_land = false;
   s_x = x;
   s_y = y;
   x_d_ = x_d;
   y_d_ = y_d;
   z_d_ = z_d;
end

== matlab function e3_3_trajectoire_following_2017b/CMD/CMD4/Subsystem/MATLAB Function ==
function [x4_, y4_, z4_] = fcn(timestamp, sim_end_time, a, b, k, bb, w1, w2,tb2, tb3, tb4)
persistent time_start;
if isempty(time_start)
     time_start = timestamp;
end

if (timestamp - time_start) < 2
    t = 0;
elseif (sim_end_time - timestamp) >=2
    t = timestamp - 2;
else
    t = sim_end_time - 4;
end
    x4_ = a*sin(w1*(t - tb4));
    y4_ = b*cos(w2*(t - tb4));
    z4_ = k*y4_+bb;

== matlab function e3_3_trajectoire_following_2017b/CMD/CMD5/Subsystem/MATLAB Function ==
function [x5_, y5_, z5_] = fcn(timestamp, sim_end_time, a, b, k, bb, w1, w2,tb2, tb3, tb4,tb5, tb6, tb7, tb8)
persistent time_start;
if isempty(time_start)
     time_start = timestamp;
end

if (timestamp - time_start) < 2
    t = 0;
elseif (sim_end_time - timestamp) >=2
    t = timestamp - 2;
else
    t = sim_end_time - 4;
end
    x5_ = a*sin(w1*(t -tb5));
    y5_ = b*cos(w2*(t -tb5));
    z5_= k*y5_+bb;

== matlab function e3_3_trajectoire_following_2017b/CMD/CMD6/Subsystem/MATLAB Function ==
function [x6_, y6_, z6_] = fcn(timestamp, sim_end_time, a, b, k, bb, w1, w2,tb2, tb3, tb4,tb5, tb6, tb7, tb8)
persistent time_start;
if isempty(time_start)
     time_start = timestamp;
end

if (timestamp - time_start) < 2
    t = 0;
elseif (sim_end_time - timestamp) >=2
    t = timestamp - 2;
else
    t = sim_end_time - 4;
end
    x6_ = a*sin(w1*(t -tb6));
    y6_ = b*cos(w2*(t -tb6));
    z6_= k*y6_+bb;

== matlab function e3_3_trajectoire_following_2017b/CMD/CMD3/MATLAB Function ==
function [x_d_, y_d_, z_d_] = fcn(x_d, y_d, z_d, timestamp, x,y,z,battery_status, sim_time_end,battery_threshold, z_d_for_land, UAV_NUM)
persistent s_x s_y s_z ready_land
if isempty(s_x)
    s_x = x;
end
if isempty(s_y)
    s_y = y;
end
if isempty(s_z)
    s_z = z;
end
if isempty(ready_land)
    ready_land = false;
end
    
battery_low = false;
for i = 1:UAV_NUM
    if battery_status(i) < battery_threshold
        battery_low = true;
        break;
    end
end
if sim_time_end - timestamp < 1
    tello_stop = true;
else
    tello_stop = false;
end
if battery_low || tello_stop
    if ~ready_land
        s_x = x;
        s_y = y;
        ready_land = true;
    end
    z_d_ = z_d_for_land;
    x_d_ = s_x;
    y_d_ = s_y;
else
   ready_land = false;
   s_x = x;
   s_y = y;
   x_d_ = x_d;
   y_d_ = y_d;
   z_d_ = z_d;
end

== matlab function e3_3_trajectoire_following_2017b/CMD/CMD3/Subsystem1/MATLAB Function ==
function [x3_, y3_, z3_] = fcn(timestamp, sim_end_time, a, b, k, bb, w1, w2,tb2, tb3, tb4)
persistent time_start;
if isempty(time_start)
     time_start = timestamp;
end

if (timestamp - time_start) < 2
    t = 0;
elseif (sim_end_time - timestamp) >=2
    t = timestamp - 2;
else
    t = sim_end_time - 4;
end


     x3_ = 0.6*sin(0.5*t);
     y3_ = 0.6*cos(0.5*t);
     z3_ = -1;

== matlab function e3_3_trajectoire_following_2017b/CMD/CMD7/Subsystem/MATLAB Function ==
function [x7_, y7_, z7_] = fcn(timestamp, sim_end_time, a, b, k, bb, w1, w2,tb2, tb3, tb4,tb5, tb6, tb7, tb8)
persistent time_start;
if isempty(time_start)
     time_start = timestamp;
end

if (timestamp - time_start) < 2
    t = 0;
elseif (sim_end_time - timestamp) >=2
    t = timestamp - 2;
else
    t = sim_end_time - 4;
end
    x7_ = a*sin(w1*(t -tb7));
    y7_ = b*cos(w2*(t -tb7));
    z7_= k*y7_+bb;

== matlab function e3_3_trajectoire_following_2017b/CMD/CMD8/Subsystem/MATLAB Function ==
function [x8_, y8_, z8_] = fcn(timestamp, sim_end_time, a, b, k, bb, w1, w2,tb2, tb3, tb4,tb5, tb6, tb7, tb8)
persistent time_start;
if isempty(time_start)
     time_start = timestamp;
end

if (timestamp - time_start) < 2
    t = 0;
elseif (sim_end_time - timestamp) >=2
    t = timestamp - 2;
else
    t = sim_end_time - 4;
end
    x8_ = a*sin(w1*(t -tb8));
    y8_ = b*cos(w2*(t -tb8));
    z8_= k*y8_+bb;

== matlab function e3_3_trajectoire_following_2017b/control system/Baseline Controller Basic/Decoupling/Coordinate trnasformation 
from inertial frame to body frame  ==
function Vec_xy  = fcn(Vec_i , psi)
%#codegen
T = [cos(psi) sin(psi) ; -sin(psi) cos(psi)] ; 
Vec_xy = T*Vec_i(1:2,1);

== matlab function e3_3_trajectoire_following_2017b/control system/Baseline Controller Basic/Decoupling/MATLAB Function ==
function y = fcn(u,a)
y = satgd(u,a);

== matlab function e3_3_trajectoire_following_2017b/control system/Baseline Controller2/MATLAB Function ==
function y = fcn(u,a)
y = satgd(u,a);

== matlab function e3_3_trajectoire_following_2017b/control system/Baseline Controller2/Position controller/Coordinate trnasformation 
from inertial frame to body frame  ==
function Vec_xy  = fcn(Vec_i , psi)
%#codegen
T = [cos(psi) sin(psi) ; -sin(psi) cos(psi)] ; 
Vec_xy = T*Vec_i(1:2,1);
